VERSION 5.7 ;
  NOWIREEXTENSIONATPIN ON ;
  DIVIDERCHAR "/" ;
  BUSBITCHARS "[]" ;
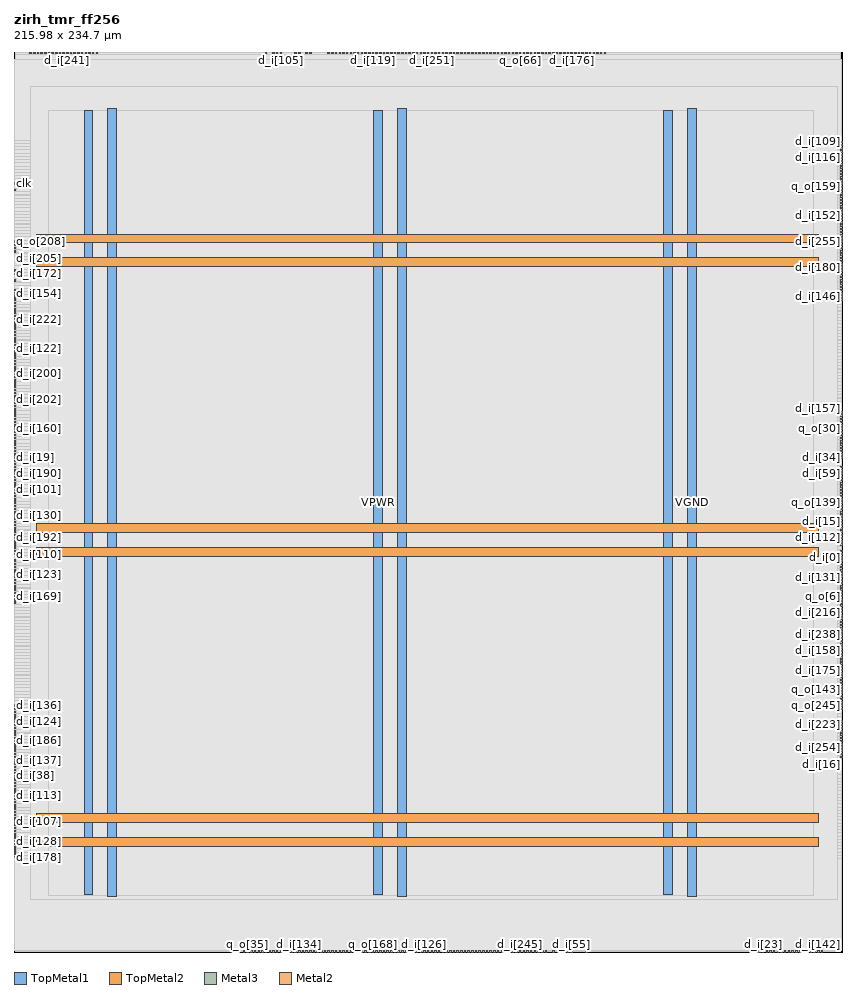
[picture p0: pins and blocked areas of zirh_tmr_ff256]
MACRO zirh_tmr_ff256
  CLASS BLOCK ;
  FOREIGN zirh_tmr_ff256 ;
  ORIGIN 0.000 0.000 ;
  SIZE 215.980 BY 234.700 ;
  PIN VGND
    DIRECTION INOUT ;
    USE GROUND ;
    PORT
      LAYER TopMetal1 ;
        RECT 24.460 14.490 26.660 219.870 ;
    END
    PORT
      LAYER TopMetal1 ;
        RECT 100.060 14.490 102.260 219.870 ;
    END
    PORT
      LAYER TopMetal1 ;
        RECT 175.660 14.490 177.860 219.870 ;
    END
    PORT
      LAYER TopMetal2 ;
        RECT 5.760 33.820 209.760 36.020 ;
    END
    PORT
      LAYER TopMetal2 ;
        RECT 5.760 109.420 209.760 111.620 ;
    END
    PORT
      LAYER TopMetal2 ;
        RECT 5.760 185.020 209.760 187.220 ;
    END
  END VGND
  PIN VPWR
    DIRECTION INOUT ;
    USE POWER ;
    PORT
      LAYER TopMetal1 ;
        RECT 18.260 14.900 20.460 219.460 ;
    END
    PORT
      LAYER TopMetal1 ;
        RECT 93.860 14.900 96.060 219.460 ;
    END
    PORT
      LAYER TopMetal1 ;
        RECT 169.460 14.900 171.660 219.460 ;
    END
    PORT
      LAYER TopMetal2 ;
        RECT 5.760 27.620 209.760 29.820 ;
    END
    PORT
      LAYER TopMetal2 ;
        RECT 5.760 103.220 209.760 105.420 ;
    END
    PORT
      LAYER TopMetal2 ;
        RECT 5.760 178.820 209.760 181.020 ;
    END
  END VPWR
  PIN clk
    DIRECTION INPUT ;
    USE SIGNAL ;
    ANTENNAGATEAREA 1.450800 ;
    PORT
      LAYER Metal3 ;
        RECT 0.000 200.140 0.400 200.540 ;
    END
  END clk
  PIN d_i[0]
    DIRECTION INPUT ;
    USE SIGNAL ;
    ANTENNAGATEAREA 0.180700 ;
    PORT
      LAYER Metal3 ;
        RECT 215.580 102.700 215.980 103.100 ;
    END
  END d_i[0]
  PIN d_i[100]
    DIRECTION INPUT ;
    USE SIGNAL ;
    ANTENNAGATEAREA 0.180700 ;
    PORT
      LAYER Metal2 ;
        RECT 83.800 234.300 84.200 234.700 ;
    END
  END d_i[100]
  PIN d_i[101]
    DIRECTION INPUT ;
    USE SIGNAL ;
    ANTENNAGATEAREA 0.180700 ;
    PORT
      LAYER Metal3 ;
        RECT 0.000 120.340 0.400 120.740 ;
    END
  END d_i[101]
  PIN d_i[102]
    DIRECTION INPUT ;
    USE SIGNAL ;
    ANTENNAGATEAREA 0.180700 ;
    PORT
      LAYER Metal3 ;
        RECT 0.000 132.100 0.400 132.500 ;
    END
  END d_i[102]
  PIN d_i[103]
    DIRECTION INPUT ;
    USE SIGNAL ;
    ANTENNAGATEAREA 0.180700 ;
    PORT
      LAYER Metal2 ;
        RECT 111.640 234.300 112.040 234.700 ;
    END
  END d_i[103]
  PIN d_i[104]
    DIRECTION INPUT ;
    USE SIGNAL ;
    ANTENNAGATEAREA 0.180700 ;
    PORT
      LAYER Metal3 ;
        RECT 0.000 24.580 0.400 24.980 ;
    END
  END d_i[104]
  PIN d_i[105]
    DIRECTION INPUT ;
    USE SIGNAL ;
    ANTENNAGATEAREA 0.180700 ;
    PORT
      LAYER Metal2 ;
        RECT 69.400 234.300 69.800 234.700 ;
    END
  END d_i[105]
  PIN d_i[106]
    DIRECTION INPUT ;
    USE SIGNAL ;
    ANTENNAGATEAREA 0.180700 ;
    PORT
      LAYER Metal3 ;
        RECT 215.580 114.460 215.980 114.860 ;
    END
  END d_i[106]
  PIN d_i[107]
    DIRECTION INPUT ;
    USE SIGNAL ;
    ANTENNAGATEAREA 0.180700 ;
    PORT
      LAYER Metal3 ;
        RECT 0.000 33.820 0.400 34.220 ;
    END
  END d_i[107]
  PIN d_i[108]
    DIRECTION INPUT ;
    USE SIGNAL ;
    ANTENNAGATEAREA 0.180700 ;
    PORT
      LAYER Metal3 ;
        RECT 0.000 172.420 0.400 172.820 ;
    END
  END d_i[108]
  PIN d_i[109]
    DIRECTION INPUT ;
    USE SIGNAL ;
    ANTENNAGATEAREA 0.180700 ;
    PORT
      LAYER Metal3 ;
        RECT 215.580 211.060 215.980 211.460 ;
    END
  END d_i[109]
  PIN d_i[10]
    DIRECTION INPUT ;
    USE SIGNAL ;
    ANTENNAGATEAREA 0.180700 ;
    PORT
      LAYER Metal2 ;
        RECT 109.720 234.300 110.120 234.700 ;
    END
  END d_i[10]
  PIN d_i[110]
    DIRECTION INPUT ;
    USE SIGNAL ;
    ANTENNAGATEAREA 0.180700 ;
    PORT
      LAYER Metal3 ;
        RECT 0.000 103.540 0.400 103.940 ;
    END
  END d_i[110]
  PIN d_i[111]
    DIRECTION INPUT ;
    USE SIGNAL ;
    ANTENNAGATEAREA 0.180700 ;
    PORT
      LAYER Metal3 ;
        RECT 215.580 188.380 215.980 188.780 ;
    END
  END d_i[111]
  PIN d_i[112]
    DIRECTION INPUT ;
    USE SIGNAL ;
    ANTENNAGATEAREA 0.180700 ;
    PORT
      LAYER Metal3 ;
        RECT 215.580 106.060 215.980 106.460 ;
    END
  END d_i[112]
  PIN d_i[113]
    DIRECTION INPUT ;
    USE SIGNAL ;
    ANTENNAGATEAREA 0.180700 ;
    PORT
      LAYER Metal3 ;
        RECT 0.000 40.540 0.400 40.940 ;
    END
  END d_i[113]
  PIN d_i[114]
    DIRECTION INPUT ;
    USE SIGNAL ;
    ANTENNAGATEAREA 0.180700 ;
    PORT
      LAYER Metal2 ;
        RECT 129.880 0.000 130.280 0.400 ;
    END
  END d_i[114]
  PIN d_i[115]
    DIRECTION INPUT ;
    USE SIGNAL ;
    ANTENNAGATEAREA 0.180700 ;
    PORT
      LAYER Metal2 ;
        RECT 153.880 234.300 154.280 234.700 ;
    END
  END d_i[115]
  PIN d_i[116]
    DIRECTION INPUT ;
    USE SIGNAL ;
    ANTENNAGATEAREA 0.180700 ;
    PORT
      LAYER Metal3 ;
        RECT 215.580 206.860 215.980 207.260 ;
    END
  END d_i[116]
  PIN d_i[117]
    DIRECTION INPUT ;
    USE SIGNAL ;
    ANTENNAGATEAREA 0.180700 ;
    PORT
      LAYER Metal3 ;
        RECT 0.000 147.220 0.400 147.620 ;
    END
  END d_i[117]
  PIN d_i[118]
    DIRECTION INPUT ;
    USE SIGNAL ;
    ANTENNAGATEAREA 0.180700 ;
    PORT
      LAYER Metal2 ;
        RECT 152.920 234.300 153.320 234.700 ;
    END
  END d_i[118]
  PIN d_i[119]
    DIRECTION INPUT ;
    USE SIGNAL ;
    ANTENNAGATEAREA 0.180700 ;
    PORT
      LAYER Metal2 ;
        RECT 93.400 234.300 93.800 234.700 ;
    END
  END d_i[119]
  PIN d_i[11]
    DIRECTION INPUT ;
    USE SIGNAL ;
    ANTENNAGATEAREA 0.180700 ;
    PORT
      LAYER Metal2 ;
        RECT 103.000 0.000 103.400 0.400 ;
    END
  END d_i[11]
  PIN d_i[120]
    DIRECTION INPUT ;
    USE SIGNAL ;
    ANTENNAGATEAREA 0.180700 ;
    PORT
      LAYER Metal3 ;
        RECT 215.580 69.940 215.980 70.340 ;
    END
  END d_i[120]
  PIN d_i[121]
    DIRECTION INPUT ;
    USE SIGNAL ;
    ANTENNAGATEAREA 0.180700 ;
    PORT
      LAYER Metal2 ;
        RECT 59.800 0.000 60.200 0.400 ;
    END
  END d_i[121]
  PIN d_i[122]
    DIRECTION INPUT ;
    USE SIGNAL ;
    ANTENNAGATEAREA 0.180700 ;
    PORT
      LAYER Metal3 ;
        RECT 0.000 157.300 0.400 157.700 ;
    END
  END d_i[122]
  PIN d_i[123]
    DIRECTION INPUT ;
    USE SIGNAL ;
    ANTENNAGATEAREA 0.180700 ;
    PORT
      LAYER Metal3 ;
        RECT 0.000 100.180 0.400 100.580 ;
    END
  END d_i[123]
  PIN d_i[124]
    DIRECTION INPUT ;
    USE SIGNAL ;
    ANTENNAGATEAREA 0.180700 ;
    PORT
      LAYER Metal3 ;
        RECT 0.000 59.860 0.400 60.260 ;
    END
  END d_i[124]
  PIN d_i[125]
    DIRECTION INPUT ;
    USE SIGNAL ;
    ANTENNAGATEAREA 0.180700 ;
    PORT
      LAYER Metal3 ;
        RECT 0.000 96.820 0.400 97.220 ;
    END
  END d_i[125]
  PIN d_i[126]
    DIRECTION INPUT ;
    USE SIGNAL ;
    ANTENNAGATEAREA 0.180700 ;
    PORT
      LAYER Metal2 ;
        RECT 106.840 0.000 107.240 0.400 ;
    END
  END d_i[126]
  PIN d_i[127]
    DIRECTION INPUT ;
    USE SIGNAL ;
    ANTENNAGATEAREA 0.180700 ;
    PORT
      LAYER Metal3 ;
        RECT 0.000 35.500 0.400 35.900 ;
    END
  END d_i[127]
  PIN d_i[128]
    DIRECTION INPUT ;
    USE SIGNAL ;
    ANTENNAGATEAREA 0.180700 ;
    PORT
      LAYER Metal3 ;
        RECT 0.000 30.460 0.400 30.860 ;
    END
  END d_i[128]
  PIN d_i[129]
    DIRECTION INPUT ;
    USE SIGNAL ;
    ANTENNAGATEAREA 0.180700 ;
    PORT
      LAYER Metal2 ;
        RECT 126.040 0.000 126.440 0.400 ;
    END
  END d_i[129]
  PIN d_i[12]
    DIRECTION INPUT ;
    USE SIGNAL ;
    ANTENNAGATEAREA 0.180700 ;
    PORT
      LAYER Metal3 ;
        RECT 0.000 132.940 0.400 133.340 ;
    END
  END d_i[12]
  PIN d_i[130]
    DIRECTION INPUT ;
    USE SIGNAL ;
    ANTENNAGATEAREA 0.180700 ;
    PORT
      LAYER Metal3 ;
        RECT 0.000 113.620 0.400 114.020 ;
    END
  END d_i[130]
  PIN d_i[131]
    DIRECTION INPUT ;
    USE SIGNAL ;
    ANTENNAGATEAREA 0.180700 ;
    PORT
      LAYER Metal3 ;
        RECT 215.580 99.340 215.980 99.740 ;
    END
  END d_i[131]
  PIN d_i[132]
    DIRECTION INPUT ;
    USE SIGNAL ;
    ANTENNAGATEAREA 0.180700 ;
    PORT
      LAYER Metal3 ;
        RECT 0.000 145.540 0.400 145.940 ;
    END
  END d_i[132]
  PIN d_i[133]
    DIRECTION INPUT ;
    USE SIGNAL ;
    ANTENNAGATEAREA 0.180700 ;
    PORT
      LAYER Metal2 ;
        RECT 71.320 0.000 71.720 0.400 ;
    END
  END d_i[133]
  PIN d_i[134]
    DIRECTION INPUT ;
    USE SIGNAL ;
    ANTENNAGATEAREA 0.180700 ;
    PORT
      LAYER Metal2 ;
        RECT 74.200 0.000 74.600 0.400 ;
    END
  END d_i[134]
  PIN d_i[135]
    DIRECTION INPUT ;
    USE SIGNAL ;
    ANTENNAGATEAREA 0.180700 ;
    PORT
      LAYER Metal2 ;
        RECT 127.960 0.000 128.360 0.400 ;
    END
  END d_i[135]
  PIN d_i[136]
    DIRECTION INPUT ;
    USE SIGNAL ;
    ANTENNAGATEAREA 0.180700 ;
    PORT
      LAYER Metal3 ;
        RECT 0.000 64.060 0.400 64.460 ;
    END
  END d_i[136]
  PIN d_i[137]
    DIRECTION INPUT ;
    USE SIGNAL ;
    ANTENNAGATEAREA 0.180700 ;
    PORT
      LAYER Metal3 ;
        RECT 0.000 49.780 0.400 50.180 ;
    END
  END d_i[137]
  PIN d_i[138]
    DIRECTION INPUT ;
    USE SIGNAL ;
    ANTENNAGATEAREA 0.180700 ;
    PORT
      LAYER Metal3 ;
        RECT 215.580 206.020 215.980 206.420 ;
    END
  END d_i[138]
  PIN d_i[139]
    DIRECTION INPUT ;
    USE SIGNAL ;
    ANTENNAGATEAREA 0.180700 ;
    PORT
      LAYER Metal3 ;
        RECT 215.580 115.300 215.980 115.700 ;
    END
  END d_i[139]
  PIN d_i[13]
    DIRECTION INPUT ;
    USE SIGNAL ;
    ANTENNAGATEAREA 0.180700 ;
    PORT
      LAYER Metal2 ;
        RECT 121.240 234.300 121.640 234.700 ;
    END
  END d_i[13]
  PIN d_i[140]
    DIRECTION INPUT ;
    USE SIGNAL ;
    ANTENNAGATEAREA 0.180700 ;
    PORT
      LAYER Metal3 ;
        RECT 215.580 72.460 215.980 72.860 ;
    END
  END d_i[140]
  PIN d_i[141]
    DIRECTION INPUT ;
    USE SIGNAL ;
    ANTENNAGATEAREA 0.180700 ;
    PORT
      LAYER Metal3 ;
        RECT 0.000 134.620 0.400 135.020 ;
    END
  END d_i[141]
  PIN d_i[142]
    DIRECTION INPUT ;
    USE SIGNAL ;
    ANTENNAGATEAREA 0.180700 ;
    PORT
      LAYER Metal2 ;
        RECT 210.520 0.000 210.920 0.400 ;
    END
  END d_i[142]
  PIN d_i[143]
    DIRECTION INPUT ;
    USE SIGNAL ;
    ANTENNAGATEAREA 0.180700 ;
    PORT
      LAYER Metal3 ;
        RECT 215.580 66.580 215.980 66.980 ;
    END
  END d_i[143]
  PIN d_i[144]
    DIRECTION INPUT ;
    USE SIGNAL ;
    ANTENNAGATEAREA 0.180700 ;
    PORT
      LAYER Metal3 ;
        RECT 0.000 61.540 0.400 61.940 ;
    END
  END d_i[144]
  PIN d_i[145]
    DIRECTION INPUT ;
    USE SIGNAL ;
    ANTENNAGATEAREA 0.180700 ;
    PORT
      LAYER Metal3 ;
        RECT 0.000 95.140 0.400 95.540 ;
    END
  END d_i[145]
  PIN d_i[146]
    DIRECTION INPUT ;
    USE SIGNAL ;
    ANTENNAGATEAREA 0.180700 ;
    PORT
      LAYER Metal3 ;
        RECT 215.580 170.740 215.980 171.140 ;
    END
  END d_i[146]
  PIN d_i[147]
    DIRECTION INPUT ;
    USE SIGNAL ;
    ANTENNAGATEAREA 0.180700 ;
    PORT
      LAYER Metal2 ;
        RECT 73.240 0.000 73.640 0.400 ;
    END
  END d_i[147]
  PIN d_i[148]
    DIRECTION INPUT ;
    USE SIGNAL ;
    ANTENNAGATEAREA 0.180700 ;
    PORT
      LAYER Metal2 ;
        RECT 69.400 0.000 69.800 0.400 ;
    END
  END d_i[148]
  PIN d_i[149]
    DIRECTION INPUT ;
    USE SIGNAL ;
    ANTENNAGATEAREA 0.180700 ;
    PORT
      LAYER Metal3 ;
        RECT 0.000 122.860 0.400 123.260 ;
    END
  END d_i[149]
  PIN d_i[14]
    DIRECTION INPUT ;
    USE SIGNAL ;
    ANTENNAGATEAREA 0.180700 ;
    PORT
      LAYER Metal3 ;
        RECT 0.000 162.340 0.400 162.740 ;
    END
  END d_i[14]
  PIN d_i[150]
    DIRECTION INPUT ;
    USE SIGNAL ;
    ANTENNAGATEAREA 0.180700 ;
    PORT
      LAYER Metal3 ;
        RECT 215.580 107.740 215.980 108.140 ;
    END
  END d_i[150]
  PIN d_i[151]
    DIRECTION INPUT ;
    USE SIGNAL ;
    ANTENNAGATEAREA 0.180700 ;
    PORT
      LAYER Metal2 ;
        RECT 4.120 234.300 4.520 234.700 ;
    END
  END d_i[151]
  PIN d_i[152]
    DIRECTION INPUT ;
    USE SIGNAL ;
    ANTENNAGATEAREA 0.180700 ;
    PORT
      LAYER Metal3 ;
        RECT 215.580 191.740 215.980 192.140 ;
    END
  END d_i[152]
  PIN d_i[153]
    DIRECTION INPUT ;
    USE SIGNAL ;
    ANTENNAGATEAREA 0.180700 ;
    PORT
      LAYER Metal2 ;
        RECT 97.240 0.000 97.640 0.400 ;
    END
  END d_i[153]
  PIN d_i[154]
    DIRECTION INPUT ;
    USE SIGNAL ;
    ANTENNAGATEAREA 0.180700 ;
    PORT
      LAYER Metal3 ;
        RECT 0.000 171.580 0.400 171.980 ;
    END
  END d_i[154]
  PIN d_i[155]
    DIRECTION INPUT ;
    USE SIGNAL ;
    ANTENNAGATEAREA 0.180700 ;
    PORT
      LAYER Metal3 ;
        RECT 0.000 112.780 0.400 113.180 ;
    END
  END d_i[155]
  PIN d_i[156]
    DIRECTION INPUT ;
    USE SIGNAL ;
    ANTENNAGATEAREA 0.180700 ;
    PORT
      LAYER Metal2 ;
        RECT 199.000 0.000 199.400 0.400 ;
    END
  END d_i[156]
  PIN d_i[157]
    DIRECTION INPUT ;
    USE SIGNAL ;
    ANTENNAGATEAREA 0.180700 ;
    PORT
      LAYER Metal3 ;
        RECT 215.580 139.660 215.980 140.060 ;
    END
  END d_i[157]
  PIN d_i[158]
    DIRECTION INPUT ;
    USE SIGNAL ;
    ANTENNAGATEAREA 0.180700 ;
    PORT
      LAYER Metal3 ;
        RECT 215.580 78.340 215.980 78.740 ;
    END
  END d_i[158]
  PIN d_i[159]
    DIRECTION INPUT ;
    USE SIGNAL ;
    ANTENNAGATEAREA 0.180700 ;
    PORT
      LAYER Metal3 ;
        RECT 215.580 197.620 215.980 198.020 ;
    END
  END d_i[159]
  PIN d_i[15]
    DIRECTION INPUT ;
    USE SIGNAL ;
    ANTENNAGATEAREA 0.180700 ;
    PORT
      LAYER Metal3 ;
        RECT 215.580 110.260 215.980 110.660 ;
    END
  END d_i[15]
  PIN d_i[160]
    DIRECTION INPUT ;
    USE SIGNAL ;
    ANTENNAGATEAREA 0.180700 ;
    PORT
      LAYER Metal3 ;
        RECT 0.000 136.300 0.400 136.700 ;
    END
  END d_i[160]
  PIN d_i[161]
    DIRECTION INPUT ;
    USE SIGNAL ;
    ANTENNAGATEAREA 0.180700 ;
    PORT
      LAYER Metal2 ;
        RECT 207.640 0.000 208.040 0.400 ;
    END
  END d_i[161]
  PIN d_i[162]
    DIRECTION INPUT ;
    USE SIGNAL ;
    ANTENNAGATEAREA 0.180700 ;
    PORT
      LAYER Metal3 ;
        RECT 215.580 184.180 215.980 184.580 ;
    END
  END d_i[162]
  PIN d_i[163]
    DIRECTION INPUT ;
    USE SIGNAL ;
    ANTENNAGATEAREA 0.180700 ;
    PORT
      LAYER Metal3 ;
        RECT 215.580 109.420 215.980 109.820 ;
    END
  END d_i[163]
  PIN d_i[164]
    DIRECTION INPUT ;
    USE SIGNAL ;
    ANTENNAGATEAREA 0.180700 ;
    PORT
      LAYER Metal3 ;
        RECT 0.000 105.220 0.400 105.620 ;
    END
  END d_i[164]
  PIN d_i[165]
    DIRECTION INPUT ;
    USE SIGNAL ;
    ANTENNAGATEAREA 0.180700 ;
    PORT
      LAYER Metal3 ;
        RECT 215.580 175.780 215.980 176.180 ;
    END
  END d_i[165]
  PIN d_i[166]
    DIRECTION INPUT ;
    USE SIGNAL ;
    ANTENNAGATEAREA 0.180700 ;
    PORT
      LAYER Metal2 ;
        RECT 123.160 0.000 123.560 0.400 ;
    END
  END d_i[166]
  PIN d_i[167]
    DIRECTION INPUT ;
    USE SIGNAL ;
    ANTENNAGATEAREA 0.180700 ;
    PORT
      LAYER Metal3 ;
        RECT 0.000 41.380 0.400 41.780 ;
    END
  END d_i[167]
  PIN d_i[168]
    DIRECTION INPUT ;
    USE SIGNAL ;
    ANTENNAGATEAREA 0.180700 ;
    PORT
      LAYER Metal2 ;
        RECT 79.960 0.000 80.360 0.400 ;
    END
  END d_i[168]
  PIN d_i[169]
    DIRECTION INPUT ;
    USE SIGNAL ;
    ANTENNAGATEAREA 0.180700 ;
    PORT
      LAYER Metal3 ;
        RECT 0.000 92.620 0.400 93.020 ;
    END
  END d_i[169]
  PIN d_i[16]
    DIRECTION INPUT ;
    USE SIGNAL ;
    ANTENNAGATEAREA 0.180700 ;
    PORT
      LAYER Metal3 ;
        RECT 215.580 50.620 215.980 51.020 ;
    END
  END d_i[16]
  PIN d_i[170]
    DIRECTION INPUT ;
    USE SIGNAL ;
    ANTENNAGATEAREA 0.180700 ;
    PORT
      LAYER Metal2 ;
        RECT 95.320 234.300 95.720 234.700 ;
    END
  END d_i[170]
  PIN d_i[171]
    DIRECTION INPUT ;
    USE SIGNAL ;
    ANTENNAGATEAREA 0.180700 ;
    PORT
      LAYER Metal3 ;
        RECT 0.000 127.060 0.400 127.460 ;
    END
  END d_i[171]
  PIN d_i[172]
    DIRECTION INPUT ;
    USE SIGNAL ;
    ANTENNAGATEAREA 0.180700 ;
    PORT
      LAYER Metal3 ;
        RECT 0.000 176.620 0.400 177.020 ;
    END
  END d_i[172]
  PIN d_i[173]
    DIRECTION INPUT ;
    USE SIGNAL ;
    ANTENNAGATEAREA 0.180700 ;
    PORT
      LAYER Metal3 ;
        RECT 0.000 116.980 0.400 117.380 ;
    END
  END d_i[173]
  PIN d_i[174]
    DIRECTION INPUT ;
    USE SIGNAL ;
    ANTENNAGATEAREA 0.180700 ;
    PORT
      LAYER Metal3 ;
        RECT 0.000 37.180 0.400 37.580 ;
    END
  END d_i[174]
  PIN d_i[175]
    DIRECTION INPUT ;
    USE SIGNAL ;
    ANTENNAGATEAREA 0.180700 ;
    PORT
      LAYER Metal3 ;
        RECT 215.580 74.980 215.980 75.380 ;
    END
  END d_i[175]
  PIN d_i[176]
    DIRECTION INPUT ;
    USE SIGNAL ;
    ANTENNAGATEAREA 0.180700 ;
    PORT
      LAYER Metal2 ;
        RECT 145.240 234.300 145.640 234.700 ;
    END
  END d_i[176]
  PIN d_i[177]
    DIRECTION INPUT ;
    USE SIGNAL ;
    ANTENNAGATEAREA 0.180700 ;
    PORT
      LAYER Metal2 ;
        RECT 104.920 234.300 105.320 234.700 ;
    END
  END d_i[177]
  PIN d_i[178]
    DIRECTION INPUT ;
    USE SIGNAL ;
    ANTENNAGATEAREA 0.180700 ;
    PORT
      LAYER Metal3 ;
        RECT 0.000 26.260 0.400 26.660 ;
    END
  END d_i[178]
  PIN d_i[179]
    DIRECTION INPUT ;
    USE SIGNAL ;
    ANTENNAGATEAREA 0.180700 ;
    PORT
      LAYER Metal3 ;
        RECT 0.000 99.340 0.400 99.740 ;
    END
  END d_i[179]
  PIN d_i[17]
    DIRECTION INPUT ;
    USE SIGNAL ;
    ANTENNAGATEAREA 0.180700 ;
    PORT
      LAYER Metal2 ;
        RECT 146.200 234.300 146.600 234.700 ;
    END
  END d_i[17]
  PIN d_i[180]
    DIRECTION INPUT ;
    USE SIGNAL ;
    ANTENNAGATEAREA 0.180700 ;
    PORT
      LAYER Metal3 ;
        RECT 215.580 178.300 215.980 178.700 ;
    END
  END d_i[180]
  PIN d_i[181]
    DIRECTION INPUT ;
    USE SIGNAL ;
    ANTENNAGATEAREA 0.180700 ;
    PORT
      LAYER Metal2 ;
        RECT 204.760 0.000 205.160 0.400 ;
    END
  END d_i[181]
  PIN d_i[182]
    DIRECTION INPUT ;
    USE SIGNAL ;
    ANTENNAGATEAREA 0.180700 ;
    PORT
      LAYER Metal3 ;
        RECT 215.580 52.300 215.980 52.700 ;
    END
  END d_i[182]
  PIN d_i[183]
    DIRECTION INPUT ;
    USE SIGNAL ;
    ANTENNAGATEAREA 0.180700 ;
    PORT
      LAYER Metal3 ;
        RECT 0.000 114.460 0.400 114.860 ;
    END
  END d_i[183]
  PIN d_i[184]
    DIRECTION INPUT ;
    USE SIGNAL ;
    ANTENNAGATEAREA 0.180700 ;
    PORT
      LAYER Metal3 ;
        RECT 0.000 174.940 0.400 175.340 ;
    END
  END d_i[184]
  PIN d_i[185]
    DIRECTION INPUT ;
    USE SIGNAL ;
    ANTENNAGATEAREA 0.180700 ;
    PORT
      LAYER Metal2 ;
        RECT 61.720 0.000 62.120 0.400 ;
    END
  END d_i[185]
  PIN d_i[186]
    DIRECTION INPUT ;
    USE SIGNAL ;
    ANTENNAGATEAREA 0.180700 ;
    PORT
      LAYER Metal3 ;
        RECT 0.000 53.140 0.400 53.540 ;
    END
  END d_i[186]
  PIN d_i[187]
    DIRECTION INPUT ;
    USE SIGNAL ;
    ANTENNAGATEAREA 0.180700 ;
    PORT
      LAYER Metal3 ;
        RECT 0.000 27.940 0.400 28.340 ;
    END
  END d_i[187]
  PIN d_i[188]
    DIRECTION INPUT ;
    USE SIGNAL ;
    ANTENNAGATEAREA 0.180700 ;
    PORT
      LAYER Metal2 ;
        RECT 83.800 0.000 84.200 0.400 ;
    END
  END d_i[188]
  PIN d_i[189]
    DIRECTION INPUT ;
    USE SIGNAL ;
    ANTENNAGATEAREA 0.180700 ;
    PORT
      LAYER Metal2 ;
        RECT 86.680 0.000 87.080 0.400 ;
    END
  END d_i[189]
  PIN d_i[18]
    DIRECTION INPUT ;
    USE SIGNAL ;
    ANTENNAGATEAREA 0.180700 ;
    PORT
      LAYER Metal2 ;
        RECT 68.440 0.000 68.840 0.400 ;
    END
  END d_i[18]
  PIN d_i[190]
    DIRECTION INPUT ;
    USE SIGNAL ;
    ANTENNAGATEAREA 0.180700 ;
    PORT
      LAYER Metal3 ;
        RECT 0.000 124.540 0.400 124.940 ;
    END
  END d_i[190]
  PIN d_i[191]
    DIRECTION INPUT ;
    USE SIGNAL ;
    ANTENNAGATEAREA 0.180700 ;
    PORT
      LAYER Metal3 ;
        RECT 215.580 100.180 215.980 100.580 ;
    END
  END d_i[191]
  PIN d_i[192]
    DIRECTION INPUT ;
    USE SIGNAL ;
    ANTENNAGATEAREA 0.180700 ;
    PORT
      LAYER Metal3 ;
        RECT 0.000 106.060 0.400 106.460 ;
    END
  END d_i[192]
  PIN d_i[193]
    DIRECTION INPUT ;
    USE SIGNAL ;
    ANTENNAGATEAREA 0.180700 ;
    PORT
      LAYER Metal3 ;
        RECT 0.000 106.900 0.400 107.300 ;
    END
  END d_i[193]
  PIN d_i[194]
    DIRECTION INPUT ;
    USE SIGNAL ;
    ANTENNAGATEAREA 0.180700 ;
    PORT
      LAYER Metal2 ;
        RECT 151.960 234.300 152.360 234.700 ;
    END
  END d_i[194]
  PIN d_i[195]
    DIRECTION INPUT ;
    USE SIGNAL ;
    ANTENNAGATEAREA 0.180700 ;
    PORT
      LAYER Metal2 ;
        RECT 133.720 0.000 134.120 0.400 ;
    END
  END d_i[195]
  PIN d_i[196]
    DIRECTION INPUT ;
    USE SIGNAL ;
    ANTENNAGATEAREA 0.180700 ;
    PORT
      LAYER Metal3 ;
        RECT 0.000 119.500 0.400 119.900 ;
    END
  END d_i[196]
  PIN d_i[197]
    DIRECTION INPUT ;
    USE SIGNAL ;
    ANTENNAGATEAREA 0.180700 ;
    PORT
      LAYER Metal3 ;
        RECT 215.580 76.660 215.980 77.060 ;
    END
  END d_i[197]
  PIN d_i[198]
    DIRECTION INPUT ;
    USE SIGNAL ;
    ANTENNAGATEAREA 0.180700 ;
    PORT
      LAYER Metal3 ;
        RECT 0.000 163.180 0.400 163.580 ;
    END
  END d_i[198]
  PIN d_i[199]
    DIRECTION INPUT ;
    USE SIGNAL ;
    ANTENNAGATEAREA 0.180700 ;
    PORT
      LAYER Metal3 ;
        RECT 0.000 109.420 0.400 109.820 ;
    END
  END d_i[199]
  PIN d_i[19]
    DIRECTION INPUT ;
    USE SIGNAL ;
    ANTENNAGATEAREA 0.180700 ;
    PORT
      LAYER Metal3 ;
        RECT 0.000 128.740 0.400 129.140 ;
    END
  END d_i[19]
  PIN d_i[1]
    DIRECTION INPUT ;
    USE SIGNAL ;
    ANTENNAGATEAREA 0.180700 ;
    PORT
      LAYER Metal3 ;
        RECT 215.580 202.660 215.980 203.060 ;
    END
  END d_i[1]
  PIN d_i[200]
    DIRECTION INPUT ;
    USE SIGNAL ;
    ANTENNAGATEAREA 0.180700 ;
    PORT
      LAYER Metal3 ;
        RECT 0.000 150.580 0.400 150.980 ;
    END
  END d_i[200]
  PIN d_i[201]
    DIRECTION INPUT ;
    USE SIGNAL ;
    ANTENNAGATEAREA 0.180700 ;
    PORT
      LAYER Metal3 ;
        RECT 0.000 116.140 0.400 116.540 ;
    END
  END d_i[201]
  PIN d_i[202]
    DIRECTION INPUT ;
    USE SIGNAL ;
    ANTENNAGATEAREA 0.180700 ;
    PORT
      LAYER Metal3 ;
        RECT 0.000 143.860 0.400 144.260 ;
    END
  END d_i[202]
  PIN d_i[203]
    DIRECTION INPUT ;
    USE SIGNAL ;
    ANTENNAGATEAREA 0.180700 ;
    PORT
      LAYER Metal3 ;
        RECT 0.000 90.940 0.400 91.340 ;
    END
  END d_i[203]
  PIN d_i[204]
    DIRECTION INPUT ;
    USE SIGNAL ;
    ANTENNAGATEAREA 0.180700 ;
    PORT
      LAYER Metal2 ;
        RECT 7.000 234.300 7.400 234.700 ;
    END
  END d_i[204]
  PIN d_i[205]
    DIRECTION INPUT ;
    USE SIGNAL ;
    ANTENNAGATEAREA 0.180700 ;
    PORT
      LAYER Metal3 ;
        RECT 0.000 182.500 0.400 182.900 ;
    END
  END d_i[205]
  PIN d_i[206]
    DIRECTION INPUT ;
    USE SIGNAL ;
    ANTENNAGATEAREA 0.180700 ;
    PORT
      LAYER Metal3 ;
        RECT 0.000 146.380 0.400 146.780 ;
    END
  END d_i[206]
  PIN d_i[207]
    DIRECTION INPUT ;
    USE SIGNAL ;
    ANTENNAGATEAREA 0.180700 ;
    PORT
      LAYER Metal3 ;
        RECT 0.000 48.940 0.400 49.340 ;
    END
  END d_i[207]
  PIN d_i[208]
    DIRECTION INPUT ;
    USE SIGNAL ;
    ANTENNAGATEAREA 0.180700 ;
    PORT
      LAYER Metal3 ;
        RECT 0.000 184.180 0.400 184.580 ;
    END
  END d_i[208]
  PIN d_i[209]
    DIRECTION INPUT ;
    USE SIGNAL ;
    ANTENNAGATEAREA 0.180700 ;
    PORT
      LAYER Metal2 ;
        RECT 80.920 0.000 81.320 0.400 ;
    END
  END d_i[209]
  PIN d_i[20]
    DIRECTION INPUT ;
    USE SIGNAL ;
    ANTENNAGATEAREA 0.180700 ;
    PORT
      LAYER Metal3 ;
        RECT 0.000 170.740 0.400 171.140 ;
    END
  END d_i[20]
  PIN d_i[210]
    DIRECTION INPUT ;
    USE SIGNAL ;
    ANTENNAGATEAREA 0.180700 ;
    PORT
      LAYER Metal2 ;
        RECT 107.800 0.000 108.200 0.400 ;
    END
  END d_i[210]
  PIN d_i[211]
    DIRECTION INPUT ;
    USE SIGNAL ;
    ANTENNAGATEAREA 0.180700 ;
    PORT
      LAYER Metal2 ;
        RECT 138.520 234.300 138.920 234.700 ;
    END
  END d_i[211]
  PIN d_i[212]
    DIRECTION INPUT ;
    USE SIGNAL ;
    ANTENNAGATEAREA 0.180700 ;
    PORT
      LAYER Metal3 ;
        RECT 215.580 112.780 215.980 113.180 ;
    END
  END d_i[212]
  PIN d_i[213]
    DIRECTION INPUT ;
    USE SIGNAL ;
    ANTENNAGATEAREA 0.180700 ;
    PORT
      LAYER Metal3 ;
        RECT 215.580 122.860 215.980 123.260 ;
    END
  END d_i[213]
  PIN d_i[214]
    DIRECTION INPUT ;
    USE SIGNAL ;
    ANTENNAGATEAREA 0.180700 ;
    PORT
      LAYER Metal2 ;
        RECT 91.480 234.300 91.880 234.700 ;
    END
  END d_i[214]
  PIN d_i[215]
    DIRECTION INPUT ;
    USE SIGNAL ;
    ANTENNAGATEAREA 0.180700 ;
    PORT
      LAYER Metal3 ;
        RECT 215.580 201.820 215.980 202.220 ;
    END
  END d_i[215]
  PIN d_i[216]
    DIRECTION INPUT ;
    USE SIGNAL ;
    ANTENNAGATEAREA 0.180700 ;
    PORT
      LAYER Metal3 ;
        RECT 215.580 88.420 215.980 88.820 ;
    END
  END d_i[216]
  PIN d_i[217]
    DIRECTION INPUT ;
    USE SIGNAL ;
    ANTENNAGATEAREA 0.180700 ;
    PORT
      LAYER Metal2 ;
        RECT 103.960 234.300 104.360 234.700 ;
    END
  END d_i[217]
  PIN d_i[218]
    DIRECTION INPUT ;
    USE SIGNAL ;
    ANTENNAGATEAREA 0.180700 ;
    PORT
      LAYER Metal2 ;
        RECT 105.880 0.000 106.280 0.400 ;
    END
  END d_i[218]
  PIN d_i[219]
    DIRECTION INPUT ;
    USE SIGNAL ;
    ANTENNAGATEAREA 0.180700 ;
    PORT
      LAYER Metal2 ;
        RECT 125.080 0.000 125.480 0.400 ;
    END
  END d_i[219]
  PIN d_i[21]
    DIRECTION INPUT ;
    USE SIGNAL ;
    ANTENNAGATEAREA 0.180700 ;
    PORT
      LAYER Metal2 ;
        RECT 123.160 234.300 123.560 234.700 ;
    END
  END d_i[21]
  PIN d_i[220]
    DIRECTION INPUT ;
    USE SIGNAL ;
    ANTENNAGATEAREA 0.180700 ;
    PORT
      LAYER Metal2 ;
        RECT 129.880 234.300 130.280 234.700 ;
    END
  END d_i[220]
  PIN d_i[221]
    DIRECTION INPUT ;
    USE SIGNAL ;
    ANTENNAGATEAREA 0.180700 ;
    PORT
      LAYER Metal3 ;
        RECT 0.000 108.580 0.400 108.980 ;
    END
  END d_i[221]
  PIN d_i[222]
    DIRECTION INPUT ;
    USE SIGNAL ;
    ANTENNAGATEAREA 0.180700 ;
    PORT
      LAYER Metal3 ;
        RECT 0.000 164.860 0.400 165.260 ;
    END
  END d_i[222]
  PIN d_i[223]
    DIRECTION INPUT ;
    USE SIGNAL ;
    ANTENNAGATEAREA 0.180700 ;
    PORT
      LAYER Metal3 ;
        RECT 215.580 59.020 215.980 59.420 ;
    END
  END d_i[223]
  PIN d_i[224]
    DIRECTION INPUT ;
    USE SIGNAL ;
    ANTENNAGATEAREA 0.180700 ;
    PORT
      LAYER Metal3 ;
        RECT 0.000 140.500 0.400 140.900 ;
    END
  END d_i[224]
  PIN d_i[225]
    DIRECTION INPUT ;
    USE SIGNAL ;
    ANTENNAGATEAREA 0.180700 ;
    PORT
      LAYER Metal2 ;
        RECT 148.120 234.300 148.520 234.700 ;
    END
  END d_i[225]
  PIN d_i[226]
    DIRECTION INPUT ;
    USE SIGNAL ;
    ANTENNAGATEAREA 0.180700 ;
    PORT
      LAYER Metal2 ;
        RECT 137.560 234.300 137.960 234.700 ;
    END
  END d_i[226]
  PIN d_i[227]
    DIRECTION INPUT ;
    USE SIGNAL ;
    ANTENNAGATEAREA 0.180700 ;
    PORT
      LAYER Metal3 ;
        RECT 0.000 54.820 0.400 55.220 ;
    END
  END d_i[227]
  PIN d_i[228]
    DIRECTION INPUT ;
    USE SIGNAL ;
    ANTENNAGATEAREA 0.180700 ;
    PORT
      LAYER Metal2 ;
        RECT 122.200 0.000 122.600 0.400 ;
    END
  END d_i[228]
  PIN d_i[229]
    DIRECTION INPUT ;
    USE SIGNAL ;
    ANTENNAGATEAREA 0.180700 ;
    PORT
      LAYER Metal3 ;
        RECT 0.000 158.980 0.400 159.380 ;
    END
  END d_i[229]
  PIN d_i[22]
    DIRECTION INPUT ;
    USE SIGNAL ;
    ANTENNAGATEAREA 0.180700 ;
    PORT
      LAYER Metal2 ;
        RECT 112.600 0.000 113.000 0.400 ;
    END
  END d_i[22]
  PIN d_i[230]
    DIRECTION INPUT ;
    USE SIGNAL ;
    ANTENNAGATEAREA 0.180700 ;
    PORT
      LAYER Metal3 ;
        RECT 215.580 65.740 215.980 66.140 ;
    END
  END d_i[230]
  PIN d_i[231]
    DIRECTION INPUT ;
    USE SIGNAL ;
    ANTENNAGATEAREA 0.180700 ;
    PORT
      LAYER Metal3 ;
        RECT 0.000 153.100 0.400 153.500 ;
    END
  END d_i[231]
  PIN d_i[232]
    DIRECTION INPUT ;
    USE SIGNAL ;
    ANTENNAGATEAREA 0.180700 ;
    PORT
      LAYER Metal2 ;
        RECT 198.040 0.000 198.440 0.400 ;
    END
  END d_i[232]
  PIN d_i[233]
    DIRECTION INPUT ;
    USE SIGNAL ;
    ANTENNAGATEAREA 0.180700 ;
    PORT
      LAYER Metal2 ;
        RECT 120.280 234.300 120.680 234.700 ;
    END
  END d_i[233]
  PIN d_i[234]
    DIRECTION INPUT ;
    USE SIGNAL ;
    ANTENNAGATEAREA 0.180700 ;
    PORT
      LAYER Metal3 ;
        RECT 0.000 139.660 0.400 140.060 ;
    END
  END d_i[234]
  PIN d_i[235]
    DIRECTION INPUT ;
    USE SIGNAL ;
    ANTENNAGATEAREA 0.180700 ;
    PORT
      LAYER Metal2 ;
        RECT 82.840 234.300 83.240 234.700 ;
    END
  END d_i[235]
  PIN d_i[236]
    DIRECTION INPUT ;
    USE SIGNAL ;
    ANTENNAGATEAREA 0.180700 ;
    PORT
      LAYER Metal2 ;
        RECT 99.160 0.000 99.560 0.400 ;
    END
  END d_i[236]
  PIN d_i[237]
    DIRECTION INPUT ;
    USE SIGNAL ;
    ANTENNAGATEAREA 0.180700 ;
    PORT
      LAYER Metal2 ;
        RECT 203.800 0.000 204.200 0.400 ;
    END
  END d_i[237]
  PIN d_i[238]
    DIRECTION INPUT ;
    USE SIGNAL ;
    ANTENNAGATEAREA 0.180700 ;
    PORT
      LAYER Metal3 ;
        RECT 215.580 82.540 215.980 82.940 ;
    END
  END d_i[238]
  PIN d_i[239]
    DIRECTION INPUT ;
    USE SIGNAL ;
    ANTENNAGATEAREA 0.180700 ;
    PORT
      LAYER Metal3 ;
        RECT 215.580 169.900 215.980 170.300 ;
    END
  END d_i[239]
  PIN d_i[23]
    DIRECTION INPUT ;
    USE SIGNAL ;
    ANTENNAGATEAREA 0.180700 ;
    PORT
      LAYER Metal2 ;
        RECT 195.160 0.000 195.560 0.400 ;
    END
  END d_i[23]
  PIN d_i[240]
    DIRECTION INPUT ;
    USE SIGNAL ;
    ANTENNAGATEAREA 0.180700 ;
    PORT
      LAYER Metal2 ;
        RECT 130.840 0.000 131.240 0.400 ;
    END
  END d_i[240]
  PIN d_i[241]
    DIRECTION INPUT ;
    USE SIGNAL ;
    ANTENNAGATEAREA 0.180700 ;
    PORT
      LAYER Metal2 ;
        RECT 13.720 234.300 14.120 234.700 ;
    END
  END d_i[241]
  PIN d_i[242]
    DIRECTION INPUT ;
    USE SIGNAL ;
    ANTENNAGATEAREA 0.180700 ;
    PORT
      LAYER Metal3 ;
        RECT 215.580 119.500 215.980 119.900 ;
    END
  END d_i[242]
  PIN d_i[243]
    DIRECTION INPUT ;
    USE SIGNAL ;
    ANTENNAGATEAREA 0.180700 ;
    PORT
      LAYER Metal2 ;
        RECT 151.000 234.300 151.400 234.700 ;
    END
  END d_i[243]
  PIN d_i[244]
    DIRECTION INPUT ;
    USE SIGNAL ;
    ANTENNAGATEAREA 0.180700 ;
    PORT
      LAYER Metal3 ;
        RECT 215.580 86.740 215.980 87.140 ;
    END
  END d_i[244]
  PIN d_i[245]
    DIRECTION INPUT ;
    USE SIGNAL ;
    ANTENNAGATEAREA 0.180700 ;
    PORT
      LAYER Metal2 ;
        RECT 131.800 0.000 132.200 0.400 ;
    END
  END d_i[245]
  PIN d_i[246]
    DIRECTION INPUT ;
    USE SIGNAL ;
    ANTENNAGATEAREA 0.180700 ;
    PORT
      LAYER Metal2 ;
        RECT 5.080 234.300 5.480 234.700 ;
    END
  END d_i[246]
  PIN d_i[247]
    DIRECTION INPUT ;
    USE SIGNAL ;
    ANTENNAGATEAREA 0.180700 ;
    PORT
      LAYER Metal2 ;
        RECT 116.440 234.300 116.840 234.700 ;
    END
  END d_i[247]
  PIN d_i[248]
    DIRECTION INPUT ;
    USE SIGNAL ;
    ANTENNAGATEAREA 0.180700 ;
    PORT
      LAYER Metal3 ;
        RECT 0.000 58.180 0.400 58.580 ;
    END
  END d_i[248]
  PIN d_i[249]
    DIRECTION INPUT ;
    USE SIGNAL ;
    ANTENNAGATEAREA 0.180700 ;
    PORT
      LAYER Metal2 ;
        RECT 118.360 0.000 118.760 0.400 ;
    END
  END d_i[249]
  PIN d_i[24]
    DIRECTION INPUT ;
    USE SIGNAL ;
    ANTENNAGATEAREA 0.180700 ;
    PORT
      LAYER Metal2 ;
        RECT 150.040 234.300 150.440 234.700 ;
    END
  END d_i[24]
  PIN d_i[250]
    DIRECTION INPUT ;
    USE SIGNAL ;
    ANTENNAGATEAREA 0.180700 ;
    PORT
      LAYER Metal3 ;
        RECT 215.580 208.540 215.980 208.940 ;
    END
  END d_i[250]
  PIN d_i[251]
    DIRECTION INPUT ;
    USE SIGNAL ;
    ANTENNAGATEAREA 0.180700 ;
    PORT
      LAYER Metal2 ;
        RECT 108.760 234.300 109.160 234.700 ;
    END
  END d_i[251]
  PIN d_i[252]
    DIRECTION INPUT ;
    USE SIGNAL ;
    ANTENNAGATEAREA 0.180700 ;
    PORT
      LAYER Metal3 ;
        RECT 0.000 123.700 0.400 124.100 ;
    END
  END d_i[252]
  PIN d_i[253]
    DIRECTION INPUT ;
    USE SIGNAL ;
    ANTENNAGATEAREA 0.180700 ;
    PORT
      LAYER Metal2 ;
        RECT 138.520 0.000 138.920 0.400 ;
    END
  END d_i[253]
  PIN d_i[254]
    DIRECTION INPUT ;
    USE SIGNAL ;
    ANTENNAGATEAREA 0.180700 ;
    PORT
      LAYER Metal3 ;
        RECT 215.580 53.140 215.980 53.540 ;
    END
  END d_i[254]
  PIN d_i[255]
    DIRECTION INPUT ;
    USE SIGNAL ;
    ANTENNAGATEAREA 0.180700 ;
    PORT
      LAYER Metal3 ;
        RECT 215.580 185.020 215.980 185.420 ;
    END
  END d_i[255]
  PIN d_i[25]
    DIRECTION INPUT ;
    USE SIGNAL ;
    ANTENNAGATEAREA 0.180700 ;
    PORT
      LAYER Metal3 ;
        RECT 215.580 89.260 215.980 89.660 ;
    END
  END d_i[25]
  PIN d_i[26]
    DIRECTION INPUT ;
    USE SIGNAL ;
    ANTENNAGATEAREA 0.180700 ;
    PORT
      LAYER Metal3 ;
        RECT 0.000 154.780 0.400 155.180 ;
    END
  END d_i[26]
  PIN d_i[27]
    DIRECTION INPUT ;
    USE SIGNAL ;
    ANTENNAGATEAREA 0.180700 ;
    PORT
      LAYER Metal3 ;
        RECT 0.000 48.100 0.400 48.500 ;
    END
  END d_i[27]
  PIN d_i[28]
    DIRECTION INPUT ;
    USE SIGNAL ;
    ANTENNAGATEAREA 0.180700 ;
    PORT
      LAYER Metal2 ;
        RECT 77.080 234.300 77.480 234.700 ;
    END
  END d_i[28]
  PIN d_i[29]
    DIRECTION INPUT ;
    USE SIGNAL ;
    ANTENNAGATEAREA 0.180700 ;
    PORT
      LAYER Metal3 ;
        RECT 0.000 160.660 0.400 161.060 ;
    END
  END d_i[29]
  PIN d_i[2]
    DIRECTION INPUT ;
    USE SIGNAL ;
    ANTENNAGATEAREA 0.180700 ;
    PORT
      LAYER Metal2 ;
        RECT 88.600 234.300 89.000 234.700 ;
    END
  END d_i[2]
  PIN d_i[30]
    DIRECTION INPUT ;
    USE SIGNAL ;
    ANTENNAGATEAREA 0.180700 ;
    PORT
      LAYER Metal3 ;
        RECT 215.580 135.460 215.980 135.860 ;
    END
  END d_i[30]
  PIN d_i[31]
    DIRECTION INPUT ;
    USE SIGNAL ;
    ANTENNAGATEAREA 0.180700 ;
    PORT
      LAYER Metal2 ;
        RECT 101.080 234.300 101.480 234.700 ;
    END
  END d_i[31]
  PIN d_i[32]
    DIRECTION INPUT ;
    USE SIGNAL ;
    ANTENNAGATEAREA 0.180700 ;
    PORT
      LAYER Metal3 ;
        RECT 215.580 85.060 215.980 85.460 ;
    END
  END d_i[32]
  PIN d_i[33]
    DIRECTION INPUT ;
    USE SIGNAL ;
    ANTENNAGATEAREA 0.180700 ;
    PORT
      LAYER Metal3 ;
        RECT 0.000 55.660 0.400 56.060 ;
    END
  END d_i[33]
  PIN d_i[34]
    DIRECTION INPUT ;
    USE SIGNAL ;
    ANTENNAGATEAREA 0.180700 ;
    PORT
      LAYER Metal3 ;
        RECT 215.580 128.740 215.980 129.140 ;
    END
  END d_i[34]
  PIN d_i[35]
    DIRECTION INPUT ;
    USE SIGNAL ;
    ANTENNAGATEAREA 0.180700 ;
    PORT
      LAYER Metal2 ;
        RECT 62.680 0.000 63.080 0.400 ;
    END
  END d_i[35]
  PIN d_i[36]
    DIRECTION INPUT ;
    USE SIGNAL ;
    ANTENNAGATEAREA 0.180700 ;
    PORT
      LAYER Metal3 ;
        RECT 0.000 148.900 0.400 149.300 ;
    END
  END d_i[36]
  PIN d_i[37]
    DIRECTION INPUT ;
    USE SIGNAL ;
    ANTENNAGATEAREA 0.180700 ;
    PORT
      LAYER Metal2 ;
        RECT 84.760 234.300 85.160 234.700 ;
    END
  END d_i[37]
  PIN d_i[38]
    DIRECTION INPUT ;
    USE SIGNAL ;
    ANTENNAGATEAREA 0.180700 ;
    PORT
      LAYER Metal3 ;
        RECT 0.000 43.900 0.400 44.300 ;
    END
  END d_i[38]
  PIN d_i[39]
    DIRECTION INPUT ;
    USE SIGNAL ;
    ANTENNAGATEAREA 0.180700 ;
    PORT
      LAYER Metal2 ;
        RECT 144.280 234.300 144.680 234.700 ;
    END
  END d_i[39]
  PIN d_i[3]
    DIRECTION INPUT ;
    USE SIGNAL ;
    ANTENNAGATEAREA 0.180700 ;
    PORT
      LAYER Metal2 ;
        RECT 11.800 234.300 12.200 234.700 ;
    END
  END d_i[3]
  PIN d_i[40]
    DIRECTION INPUT ;
    USE SIGNAL ;
    ANTENNAGATEAREA 0.180700 ;
    PORT
      LAYER Metal3 ;
        RECT 215.580 56.500 215.980 56.900 ;
    END
  END d_i[40]
  PIN d_i[41]
    DIRECTION INPUT ;
    USE SIGNAL ;
    ANTENNAGATEAREA 0.180700 ;
    PORT
      LAYER Metal2 ;
        RECT 102.040 0.000 102.440 0.400 ;
    END
  END d_i[41]
  PIN d_i[42]
    DIRECTION INPUT ;
    USE SIGNAL ;
    ANTENNAGATEAREA 0.180700 ;
    PORT
      LAYER Metal2 ;
        RECT 127.000 234.300 127.400 234.700 ;
    END
  END d_i[42]
  PIN d_i[43]
    DIRECTION INPUT ;
    USE SIGNAL ;
    ANTENNAGATEAREA 0.180700 ;
    PORT
      LAYER Metal2 ;
        RECT 78.040 0.000 78.440 0.400 ;
    END
  END d_i[43]
  PIN d_i[44]
    DIRECTION INPUT ;
    USE SIGNAL ;
    ANTENNAGATEAREA 0.180700 ;
    PORT
      LAYER Metal3 ;
        RECT 215.580 193.420 215.980 193.820 ;
    END
  END d_i[44]
  PIN d_i[45]
    DIRECTION INPUT ;
    USE SIGNAL ;
    ANTENNAGATEAREA 0.180700 ;
    PORT
      LAYER Metal3 ;
        RECT 0.000 31.300 0.400 31.700 ;
    END
  END d_i[45]
  PIN d_i[46]
    DIRECTION INPUT ;
    USE SIGNAL ;
    ANTENNAGATEAREA 0.180700 ;
    PORT
      LAYER Metal3 ;
        RECT 215.580 174.940 215.980 175.340 ;
    END
  END d_i[46]
  PIN d_i[47]
    DIRECTION INPUT ;
    USE SIGNAL ;
    ANTENNAGATEAREA 0.180700 ;
    PORT
      LAYER Metal3 ;
        RECT 0.000 158.140 0.400 158.540 ;
    END
  END d_i[47]
  PIN d_i[48]
    DIRECTION INPUT ;
    USE SIGNAL ;
    ANTENNAGATEAREA 0.180700 ;
    PORT
      LAYER Metal2 ;
        RECT 79.000 0.000 79.400 0.400 ;
    END
  END d_i[48]
  PIN d_i[49]
    DIRECTION INPUT ;
    USE SIGNAL ;
    ANTENNAGATEAREA 0.180700 ;
    PORT
      LAYER Metal3 ;
        RECT 215.580 131.260 215.980 131.660 ;
    END
  END d_i[49]
  PIN d_i[4]
    DIRECTION INPUT ;
    USE SIGNAL ;
    ANTENNAGATEAREA 0.180700 ;
    PORT
      LAYER Metal2 ;
        RECT 85.720 234.300 86.120 234.700 ;
    END
  END d_i[4]
  PIN d_i[50]
    DIRECTION INPUT ;
    USE SIGNAL ;
    ANTENNAGATEAREA 0.180700 ;
    PORT
      LAYER Metal3 ;
        RECT 215.580 171.580 215.980 171.980 ;
    END
  END d_i[50]
  PIN d_i[51]
    DIRECTION INPUT ;
    USE SIGNAL ;
    ANTENNAGATEAREA 0.180700 ;
    PORT
      LAYER Metal2 ;
        RECT 21.400 234.300 21.800 234.700 ;
    END
  END d_i[51]
  PIN d_i[52]
    DIRECTION INPUT ;
    USE SIGNAL ;
    ANTENNAGATEAREA 0.180700 ;
    PORT
      LAYER Metal2 ;
        RECT 142.360 234.300 142.760 234.700 ;
    END
  END d_i[52]
  PIN d_i[53]
    DIRECTION INPUT ;
    USE SIGNAL ;
    ANTENNAGATEAREA 0.180700 ;
    PORT
      LAYER Metal3 ;
        RECT 0.000 167.380 0.400 167.780 ;
    END
  END d_i[53]
  PIN d_i[54]
    DIRECTION INPUT ;
    USE SIGNAL ;
    ANTENNAGATEAREA 0.180700 ;
    PORT
      LAYER Metal3 ;
        RECT 0.000 56.500 0.400 56.900 ;
    END
  END d_i[54]
  PIN d_i[55]
    DIRECTION INPUT ;
    USE SIGNAL ;
    ANTENNAGATEAREA 0.180700 ;
    PORT
      LAYER Metal2 ;
        RECT 145.240 0.000 145.640 0.400 ;
    END
  END d_i[55]
  PIN d_i[56]
    DIRECTION INPUT ;
    USE SIGNAL ;
    ANTENNAGATEAREA 0.180700 ;
    PORT
      LAYER Metal2 ;
        RECT 96.280 234.300 96.680 234.700 ;
    END
  END d_i[56]
  PIN d_i[57]
    DIRECTION INPUT ;
    USE SIGNAL ;
    ANTENNAGATEAREA 0.180700 ;
    PORT
      LAYER Metal3 ;
        RECT 215.580 94.300 215.980 94.700 ;
    END
  END d_i[57]
  PIN d_i[58]
    DIRECTION INPUT ;
    USE SIGNAL ;
    ANTENNAGATEAREA 0.180700 ;
    PORT
      LAYER Metal3 ;
        RECT 0.000 32.140 0.400 32.540 ;
    END
  END d_i[58]
  PIN d_i[59]
    DIRECTION INPUT ;
    USE SIGNAL ;
    ANTENNAGATEAREA 0.180700 ;
    PORT
      LAYER Metal3 ;
        RECT 215.580 124.540 215.980 124.940 ;
    END
  END d_i[59]
  PIN d_i[5]
    DIRECTION INPUT ;
    USE SIGNAL ;
    ANTENNAGATEAREA 0.180700 ;
    PORT
      LAYER Metal3 ;
        RECT 215.580 63.220 215.980 63.620 ;
    END
  END d_i[5]
  PIN d_i[60]
    DIRECTION INPUT ;
    USE SIGNAL ;
    ANTENNAGATEAREA 0.180700 ;
    PORT
      LAYER Metal3 ;
        RECT 215.580 200.980 215.980 201.380 ;
    END
  END d_i[60]
  PIN d_i[61]
    DIRECTION INPUT ;
    USE SIGNAL ;
    ANTENNAGATEAREA 0.180700 ;
    PORT
      LAYER Metal3 ;
        RECT 215.580 87.580 215.980 87.980 ;
    END
  END d_i[61]
  PIN d_i[62]
    DIRECTION INPUT ;
    USE SIGNAL ;
    ANTENNAGATEAREA 0.180700 ;
    PORT
      LAYER Metal3 ;
        RECT 215.580 91.780 215.980 92.180 ;
    END
  END d_i[62]
  PIN d_i[63]
    DIRECTION INPUT ;
    USE SIGNAL ;
    ANTENNAGATEAREA 0.180700 ;
    PORT
      LAYER Metal2 ;
        RECT 101.080 0.000 101.480 0.400 ;
    END
  END d_i[63]
  PIN d_i[64]
    DIRECTION INPUT ;
    USE SIGNAL ;
    ANTENNAGATEAREA 0.180700 ;
    PORT
      LAYER Metal2 ;
        RECT 113.560 0.000 113.960 0.400 ;
    END
  END d_i[64]
  PIN d_i[65]
    DIRECTION INPUT ;
    USE SIGNAL ;
    ANTENNAGATEAREA 0.180700 ;
    PORT
      LAYER Metal3 ;
        RECT 215.580 132.100 215.980 132.500 ;
    END
  END d_i[65]
  PIN d_i[66]
    DIRECTION INPUT ;
    USE SIGNAL ;
    ANTENNAGATEAREA 0.180700 ;
    PORT
      LAYER Metal2 ;
        RECT 117.400 234.300 117.800 234.700 ;
    END
  END d_i[66]
  PIN d_i[67]
    DIRECTION INPUT ;
    USE SIGNAL ;
    ANTENNAGATEAREA 0.180700 ;
    PORT
      LAYER Metal3 ;
        RECT 0.000 27.100 0.400 27.500 ;
    END
  END d_i[67]
  PIN d_i[68]
    DIRECTION INPUT ;
    USE SIGNAL ;
    ANTENNAGATEAREA 0.180700 ;
    PORT
      LAYER Metal2 ;
        RECT 18.520 234.300 18.920 234.700 ;
    END
  END d_i[68]
  PIN d_i[69]
    DIRECTION INPUT ;
    USE SIGNAL ;
    ANTENNAGATEAREA 0.180700 ;
    PORT
      LAYER Metal2 ;
        RECT 10.840 234.300 11.240 234.700 ;
    END
  END d_i[69]
  PIN d_i[6]
    DIRECTION INPUT ;
    USE SIGNAL ;
    ANTENNAGATEAREA 0.180700 ;
    PORT
      LAYER Metal3 ;
        RECT 215.580 80.020 215.980 80.420 ;
    END
  END d_i[6]
  PIN d_i[70]
    DIRECTION INPUT ;
    USE SIGNAL ;
    ANTENNAGATEAREA 0.180700 ;
    PORT
      LAYER Metal2 ;
        RECT 76.120 0.000 76.520 0.400 ;
    END
  END d_i[70]
  PIN d_i[71]
    DIRECTION INPUT ;
    USE SIGNAL ;
    ANTENNAGATEAREA 0.180700 ;
    PORT
      LAYER Metal3 ;
        RECT 0.000 52.300 0.400 52.700 ;
    END
  END d_i[71]
  PIN d_i[72]
    DIRECTION INPUT ;
    USE SIGNAL ;
    ANTENNAGATEAREA 0.180700 ;
    PORT
      LAYER Metal2 ;
        RECT 94.360 234.300 94.760 234.700 ;
    END
  END d_i[72]
  PIN d_i[73]
    DIRECTION INPUT ;
    USE SIGNAL ;
    ANTENNAGATEAREA 0.180700 ;
    PORT
      LAYER Metal3 ;
        RECT 215.580 185.860 215.980 186.260 ;
    END
  END d_i[73]
  PIN d_i[74]
    DIRECTION INPUT ;
    USE SIGNAL ;
    ANTENNAGATEAREA 0.180700 ;
    PORT
      LAYER Metal2 ;
        RECT 108.760 0.000 109.160 0.400 ;
    END
  END d_i[74]
  PIN d_i[75]
    DIRECTION INPUT ;
    USE SIGNAL ;
    ANTENNAGATEAREA 0.180700 ;
    PORT
      LAYER Metal2 ;
        RECT 98.200 234.300 98.600 234.700 ;
    END
  END d_i[75]
  PIN d_i[76]
    DIRECTION INPUT ;
    USE SIGNAL ;
    ANTENNAGATEAREA 0.180700 ;
    PORT
      LAYER Metal3 ;
        RECT 215.580 132.940 215.980 133.340 ;
    END
  END d_i[76]
  PIN d_i[77]
    DIRECTION INPUT ;
    USE SIGNAL ;
    ANTENNAGATEAREA 0.180700 ;
    PORT
      LAYER Metal2 ;
        RECT 87.640 0.000 88.040 0.400 ;
    END
  END d_i[77]
  PIN d_i[78]
    DIRECTION INPUT ;
    USE SIGNAL ;
    ANTENNAGATEAREA 0.180700 ;
    PORT
      LAYER Metal3 ;
        RECT 0.000 95.980 0.400 96.380 ;
    END
  END d_i[78]
  PIN d_i[79]
    DIRECTION INPUT ;
    USE SIGNAL ;
    ANTENNAGATEAREA 0.180700 ;
    PORT
      LAYER Metal2 ;
        RECT 200.920 0.000 201.320 0.400 ;
    END
  END d_i[79]
  PIN d_i[7]
    DIRECTION INPUT ;
    USE SIGNAL ;
    ANTENNAGATEAREA 0.180700 ;
    PORT
      LAYER Metal2 ;
        RECT 15.640 234.300 16.040 234.700 ;
    END
  END d_i[7]
  PIN d_i[80]
    DIRECTION INPUT ;
    USE SIGNAL ;
    ANTENNAGATEAREA 0.180700 ;
    PORT
      LAYER Metal3 ;
        RECT 215.580 97.660 215.980 98.060 ;
    END
  END d_i[80]
  PIN d_i[81]
    DIRECTION INPUT ;
    USE SIGNAL ;
    ANTENNAGATEAREA 0.180700 ;
    PORT
      LAYER Metal2 ;
        RECT 140.440 0.000 140.840 0.400 ;
    END
  END d_i[81]
  PIN d_i[82]
    DIRECTION INPUT ;
    USE SIGNAL ;
    ANTENNAGATEAREA 0.180700 ;
    PORT
      LAYER Metal2 ;
        RECT 9.880 234.300 10.280 234.700 ;
    END
  END d_i[82]
  PIN d_i[83]
    DIRECTION INPUT ;
    USE SIGNAL ;
    ANTENNAGATEAREA 0.180700 ;
    PORT
      LAYER Metal3 ;
        RECT 215.580 137.140 215.980 137.540 ;
    END
  END d_i[83]
  PIN d_i[84]
    DIRECTION INPUT ;
    USE SIGNAL ;
    ANTENNAGATEAREA 0.180700 ;
    PORT
      LAYER Metal3 ;
        RECT 0.000 47.260 0.400 47.660 ;
    END
  END d_i[84]
  PIN d_i[85]
    DIRECTION INPUT ;
    USE SIGNAL ;
    ANTENNAGATEAREA 0.180700 ;
    PORT
      LAYER Metal3 ;
        RECT 0.000 126.220 0.400 126.620 ;
    END
  END d_i[85]
  PIN d_i[86]
    DIRECTION INPUT ;
    USE SIGNAL ;
    ANTENNAGATEAREA 0.180700 ;
    PORT
      LAYER Metal3 ;
        RECT 215.580 113.620 215.980 114.020 ;
    END
  END d_i[86]
  PIN d_i[87]
    DIRECTION INPUT ;
    USE SIGNAL ;
    ANTENNAGATEAREA 0.180700 ;
    PORT
      LAYER Metal3 ;
        RECT 0.000 153.940 0.400 154.340 ;
    END
  END d_i[87]
  PIN d_i[88]
    DIRECTION INPUT ;
    USE SIGNAL ;
    ANTENNAGATEAREA 0.180700 ;
    PORT
      LAYER Metal3 ;
        RECT 0.000 53.980 0.400 54.380 ;
    END
  END d_i[88]
  PIN d_i[89]
    DIRECTION INPUT ;
    USE SIGNAL ;
    ANTENNAGATEAREA 0.180700 ;
    PORT
      LAYER Metal2 ;
        RECT 98.200 0.000 98.600 0.400 ;
    END
  END d_i[89]
  PIN d_i[8]
    DIRECTION INPUT ;
    USE SIGNAL ;
    ANTENNAGATEAREA 0.180700 ;
    PORT
      LAYER Metal2 ;
        RECT 8.920 234.300 9.320 234.700 ;
    END
  END d_i[8]
  PIN d_i[90]
    DIRECTION INPUT ;
    USE SIGNAL ;
    ANTENNAGATEAREA 0.180700 ;
    PORT
      LAYER Metal2 ;
        RECT 135.640 234.300 136.040 234.700 ;
    END
  END d_i[90]
  PIN d_i[91]
    DIRECTION INPUT ;
    USE SIGNAL ;
    ANTENNAGATEAREA 0.180700 ;
    PORT
      LAYER Metal3 ;
        RECT 215.580 103.540 215.980 103.940 ;
    END
  END d_i[91]
  PIN d_i[92]
    DIRECTION INPUT ;
    USE SIGNAL ;
    ANTENNAGATEAREA 0.180700 ;
    PORT
      LAYER Metal2 ;
        RECT 89.560 234.300 89.960 234.700 ;
    END
  END d_i[92]
  PIN d_i[93]
    DIRECTION INPUT ;
    USE SIGNAL ;
    ANTENNAGATEAREA 0.180700 ;
    PORT
      LAYER Metal3 ;
        RECT 215.580 57.340 215.980 57.740 ;
    END
  END d_i[93]
  PIN d_i[94]
    DIRECTION INPUT ;
    USE SIGNAL ;
    ANTENNAGATEAREA 0.180700 ;
    PORT
      LAYER Metal3 ;
        RECT 215.580 123.700 215.980 124.100 ;
    END
  END d_i[94]
  PIN d_i[95]
    DIRECTION INPUT ;
    USE SIGNAL ;
    ANTENNAGATEAREA 0.180700 ;
    PORT
      LAYER Metal3 ;
        RECT 0.000 42.220 0.400 42.620 ;
    END
  END d_i[95]
  PIN d_i[96]
    DIRECTION INPUT ;
    USE SIGNAL ;
    ANTENNAGATEAREA 0.180700 ;
    PORT
      LAYER Metal2 ;
        RECT 12.760 234.300 13.160 234.700 ;
    END
  END d_i[96]
  PIN d_i[97]
    DIRECTION INPUT ;
    USE SIGNAL ;
    ANTENNAGATEAREA 0.180700 ;
    PORT
      LAYER Metal3 ;
        RECT 215.580 71.620 215.980 72.020 ;
    END
  END d_i[97]
  PIN d_i[98]
    DIRECTION INPUT ;
    USE SIGNAL ;
    ANTENNAGATEAREA 0.180700 ;
    PORT
      LAYER Metal2 ;
        RECT 110.680 234.300 111.080 234.700 ;
    END
  END d_i[98]
  PIN d_i[99]
    DIRECTION INPUT ;
    USE SIGNAL ;
    ANTENNAGATEAREA 0.180700 ;
    PORT
      LAYER Metal2 ;
        RECT 88.600 0.000 89.000 0.400 ;
    END
  END d_i[99]
  PIN d_i[9]
    DIRECTION INPUT ;
    USE SIGNAL ;
    ANTENNAGATEAREA 0.180700 ;
    PORT
      LAYER Metal3 ;
        RECT 215.580 179.140 215.980 179.540 ;
    END
  END d_i[9]
  PIN q_o[0]
    DIRECTION OUTPUT ;
    USE SIGNAL ;
    ANTENNADIFFAREA 0.708600 ;
    PORT
      LAYER Metal3 ;
        RECT 215.580 101.860 215.980 102.260 ;
    END
  END q_o[0]
  PIN q_o[100]
    DIRECTION OUTPUT ;
    USE SIGNAL ;
    ANTENNADIFFAREA 0.708600 ;
    PORT
      LAYER Metal2 ;
        RECT 128.920 234.300 129.320 234.700 ;
    END
  END q_o[100]
  PIN q_o[101]
    DIRECTION OUTPUT ;
    USE SIGNAL ;
    ANTENNADIFFAREA 0.708600 ;
    PORT
      LAYER Metal3 ;
        RECT 0.000 122.020 0.400 122.420 ;
    END
  END q_o[101]
  PIN q_o[102]
    DIRECTION OUTPUT ;
    USE SIGNAL ;
    ANTENNADIFFAREA 0.708600 ;
    PORT
      LAYER Metal3 ;
        RECT 0.000 133.780 0.400 134.180 ;
    END
  END q_o[102]
  PIN q_o[103]
    DIRECTION OUTPUT ;
    USE SIGNAL ;
    ANTENNADIFFAREA 0.708600 ;
    PORT
      LAYER Metal2 ;
        RECT 127.960 234.300 128.360 234.700 ;
    END
  END q_o[103]
  PIN q_o[104]
    DIRECTION OUTPUT ;
    USE SIGNAL ;
    ANTENNADIFFAREA 0.708600 ;
    PORT
      LAYER Metal3 ;
        RECT 0.000 36.340 0.400 36.740 ;
    END
  END q_o[104]
  PIN q_o[105]
    DIRECTION OUTPUT ;
    USE SIGNAL ;
    ANTENNADIFFAREA 0.708600 ;
    PORT
      LAYER Metal2 ;
        RECT 81.880 234.300 82.280 234.700 ;
    END
  END q_o[105]
  PIN q_o[106]
    DIRECTION OUTPUT ;
    USE SIGNAL ;
    ANTENNADIFFAREA 0.708600 ;
    PORT
      LAYER Metal3 ;
        RECT 215.580 118.660 215.980 119.060 ;
    END
  END q_o[106]
  PIN q_o[107]
    DIRECTION OUTPUT ;
    USE SIGNAL ;
    ANTENNADIFFAREA 0.708600 ;
    PORT
      LAYER Metal2 ;
        RECT 70.360 0.000 70.760 0.400 ;
    END
  END q_o[107]
  PIN q_o[108]
    DIRECTION OUTPUT ;
    USE SIGNAL ;
    ANTENNADIFFAREA 0.708600 ;
    PORT
      LAYER Metal2 ;
        RECT 86.680 234.300 87.080 234.700 ;
    END
  END q_o[108]
  PIN q_o[109]
    DIRECTION OUTPUT ;
    USE SIGNAL ;
    ANTENNADIFFAREA 0.708600 ;
    PORT
      LAYER Metal3 ;
        RECT 215.580 189.220 215.980 189.620 ;
    END
  END q_o[109]
  PIN q_o[10]
    DIRECTION OUTPUT ;
    USE SIGNAL ;
    ANTENNADIFFAREA 0.708600 ;
    PORT
      LAYER Metal2 ;
        RECT 124.120 234.300 124.520 234.700 ;
    END
  END q_o[10]
  PIN q_o[110]
    DIRECTION OUTPUT ;
    USE SIGNAL ;
    ANTENNADIFFAREA 0.708600 ;
    PORT
      LAYER Metal3 ;
        RECT 0.000 104.380 0.400 104.780 ;
    END
  END q_o[110]
  PIN q_o[111]
    DIRECTION OUTPUT ;
    USE SIGNAL ;
    ANTENNADIFFAREA 0.708600 ;
    PORT
      LAYER Metal3 ;
        RECT 215.580 179.980 215.980 180.380 ;
    END
  END q_o[111]
  PIN q_o[112]
    DIRECTION OUTPUT ;
    USE SIGNAL ;
    ANTENNADIFFAREA 0.708600 ;
    PORT
      LAYER Metal3 ;
        RECT 215.580 106.900 215.980 107.300 ;
    END
  END q_o[112]
  PIN q_o[113]
    DIRECTION OUTPUT ;
    USE SIGNAL ;
    ANTENNADIFFAREA 0.708600 ;
    PORT
      LAYER Metal3 ;
        RECT 0.000 63.220 0.400 63.620 ;
    END
  END q_o[113]
  PIN q_o[114]
    DIRECTION OUTPUT ;
    USE SIGNAL ;
    ANTENNADIFFAREA 0.708600 ;
    PORT
      LAYER Metal2 ;
        RECT 137.560 0.000 137.960 0.400 ;
    END
  END q_o[114]
  PIN q_o[115]
    DIRECTION OUTPUT ;
    USE SIGNAL ;
    ANTENNADIFFAREA 0.708600 ;
    PORT
      LAYER Metal3 ;
        RECT 215.580 195.940 215.980 196.340 ;
    END
  END q_o[115]
  PIN q_o[116]
    DIRECTION OUTPUT ;
    USE SIGNAL ;
    ANTENNADIFFAREA 0.708600 ;
    PORT
      LAYER Metal3 ;
        RECT 215.580 195.100 215.980 195.500 ;
    END
  END q_o[116]
  PIN q_o[117]
    DIRECTION OUTPUT ;
    USE SIGNAL ;
    ANTENNADIFFAREA 0.708600 ;
    PORT
      LAYER Metal3 ;
        RECT 0.000 148.060 0.400 148.460 ;
    END
  END q_o[117]
  PIN q_o[118]
    DIRECTION OUTPUT ;
    USE SIGNAL ;
    ANTENNADIFFAREA 0.708600 ;
    PORT
      LAYER Metal2 ;
        RECT 134.680 234.300 135.080 234.700 ;
    END
  END q_o[118]
  PIN q_o[119]
    DIRECTION OUTPUT ;
    USE SIGNAL ;
    ANTENNADIFFAREA 0.708600 ;
    PORT
      LAYER Metal2 ;
        RECT 149.080 234.300 149.480 234.700 ;
    END
  END q_o[119]
  PIN q_o[11]
    DIRECTION OUTPUT ;
    USE SIGNAL ;
    ANTENNADIFFAREA 0.708600 ;
    PORT
      LAYER Metal2 ;
        RECT 120.280 0.000 120.680 0.400 ;
    END
  END q_o[11]
  PIN q_o[120]
    DIRECTION OUTPUT ;
    USE SIGNAL ;
    ANTENNADIFFAREA 0.708600 ;
    PORT
      LAYER Metal3 ;
        RECT 215.580 70.780 215.980 71.180 ;
    END
  END q_o[120]
  PIN q_o[121]
    DIRECTION OUTPUT ;
    USE SIGNAL ;
    ANTENNADIFFAREA 0.708600 ;
    PORT
      LAYER Metal2 ;
        RECT 81.880 0.000 82.280 0.400 ;
    END
  END q_o[121]
  PIN q_o[122]
    DIRECTION OUTPUT ;
    USE SIGNAL ;
    ANTENNADIFFAREA 0.708600 ;
    PORT
      LAYER Metal3 ;
        RECT 0.000 156.460 0.400 156.860 ;
    END
  END q_o[122]
  PIN q_o[123]
    DIRECTION OUTPUT ;
    USE SIGNAL ;
    ANTENNADIFFAREA 0.708600 ;
    PORT
      LAYER Metal3 ;
        RECT 0.000 101.860 0.400 102.260 ;
    END
  END q_o[123]
  PIN q_o[124]
    DIRECTION OUTPUT ;
    USE SIGNAL ;
    ANTENNADIFFAREA 0.708600 ;
    PORT
      LAYER Metal3 ;
        RECT 0.000 50.620 0.400 51.020 ;
    END
  END q_o[124]
  PIN q_o[125]
    DIRECTION OUTPUT ;
    USE SIGNAL ;
    ANTENNADIFFAREA 0.708600 ;
    PORT
      LAYER Metal3 ;
        RECT 0.000 98.500 0.400 98.900 ;
    END
  END q_o[125]
  PIN q_o[126]
    DIRECTION OUTPUT ;
    USE SIGNAL ;
    ANTENNADIFFAREA 0.708600 ;
    PORT
      LAYER Metal2 ;
        RECT 117.400 0.000 117.800 0.400 ;
    END
  END q_o[126]
  PIN q_o[127]
    DIRECTION OUTPUT ;
    USE SIGNAL ;
    ANTENNADIFFAREA 0.708600 ;
    PORT
      LAYER Metal3 ;
        RECT 0.000 38.860 0.400 39.260 ;
    END
  END q_o[127]
  PIN q_o[128]
    DIRECTION OUTPUT ;
    USE SIGNAL ;
    ANTENNADIFFAREA 0.708600 ;
    PORT
      LAYER Metal3 ;
        RECT 0.000 32.980 0.400 33.380 ;
    END
  END q_o[128]
  PIN q_o[129]
    DIRECTION OUTPUT ;
    USE SIGNAL ;
    ANTENNADIFFAREA 0.708600 ;
    PORT
      LAYER Metal3 ;
        RECT 215.580 69.100 215.980 69.500 ;
    END
  END q_o[129]
  PIN q_o[12]
    DIRECTION OUTPUT ;
    USE SIGNAL ;
    ANTENNADIFFAREA 0.708600 ;
    PORT
      LAYER Metal3 ;
        RECT 0.000 135.460 0.400 135.860 ;
    END
  END q_o[12]
  PIN q_o[130]
    DIRECTION OUTPUT ;
    USE SIGNAL ;
    ANTENNADIFFAREA 0.708600 ;
    PORT
      LAYER Metal2 ;
        RECT 100.120 0.000 100.520 0.400 ;
    END
  END q_o[130]
  PIN q_o[131]
    DIRECTION OUTPUT ;
    USE SIGNAL ;
    ANTENNADIFFAREA 0.708600 ;
    PORT
      LAYER Metal3 ;
        RECT 215.580 95.140 215.980 95.540 ;
    END
  END q_o[131]
  PIN q_o[132]
    DIRECTION OUTPUT ;
    USE SIGNAL ;
    ANTENNADIFFAREA 0.708600 ;
    PORT
      LAYER Metal3 ;
        RECT 0.000 144.700 0.400 145.100 ;
    END
  END q_o[132]
  PIN q_o[133]
    DIRECTION OUTPUT ;
    USE SIGNAL ;
    ANTENNADIFFAREA 0.708600 ;
    PORT
      LAYER Metal2 ;
        RECT 84.760 0.000 85.160 0.400 ;
    END
  END q_o[133]
  PIN q_o[134]
    DIRECTION OUTPUT ;
    USE SIGNAL ;
    ANTENNADIFFAREA 0.708600 ;
    PORT
      LAYER Metal2 ;
        RECT 90.520 0.000 90.920 0.400 ;
    END
  END q_o[134]
  PIN q_o[135]
    DIRECTION OUTPUT ;
    USE SIGNAL ;
    ANTENNADIFFAREA 0.708600 ;
    PORT
      LAYER Metal3 ;
        RECT 215.580 96.820 215.980 97.220 ;
    END
  END q_o[135]
  PIN q_o[136]
    DIRECTION OUTPUT ;
    USE SIGNAL ;
    ANTENNADIFFAREA 0.708600 ;
    PORT
      LAYER Metal3 ;
        RECT 0.000 46.420 0.400 46.820 ;
    END
  END q_o[136]
  PIN q_o[137]
    DIRECTION OUTPUT ;
    USE SIGNAL ;
    ANTENNADIFFAREA 0.708600 ;
    PORT
      LAYER Metal3 ;
        RECT 0.000 57.340 0.400 57.740 ;
    END
  END q_o[137]
  PIN q_o[138]
    DIRECTION OUTPUT ;
    USE SIGNAL ;
    ANTENNADIFFAREA 0.708600 ;
    PORT
      LAYER Metal3 ;
        RECT 215.580 205.180 215.980 205.580 ;
    END
  END q_o[138]
  PIN q_o[139]
    DIRECTION OUTPUT ;
    USE SIGNAL ;
    ANTENNADIFFAREA 0.708600 ;
    PORT
      LAYER Metal3 ;
        RECT 215.580 116.980 215.980 117.380 ;
    END
  END q_o[139]
  PIN q_o[13]
    DIRECTION OUTPUT ;
    USE SIGNAL ;
    ANTENNADIFFAREA 0.708600 ;
    PORT
      LAYER Metal3 ;
        RECT 215.580 122.020 215.980 122.420 ;
    END
  END q_o[13]
  PIN q_o[140]
    DIRECTION OUTPUT ;
    USE SIGNAL ;
    ANTENNADIFFAREA 0.708600 ;
    PORT
      LAYER Metal3 ;
        RECT 215.580 74.140 215.980 74.540 ;
    END
  END q_o[140]
  PIN q_o[141]
    DIRECTION OUTPUT ;
    USE SIGNAL ;
    ANTENNADIFFAREA 0.708600 ;
    PORT
      LAYER Metal3 ;
        RECT 0.000 137.140 0.400 137.540 ;
    END
  END q_o[141]
  PIN q_o[142]
    DIRECTION OUTPUT ;
    USE SIGNAL ;
    ANTENNADIFFAREA 0.708600 ;
    PORT
      LAYER Metal2 ;
        RECT 209.560 0.000 209.960 0.400 ;
    END
  END q_o[142]
  PIN q_o[143]
    DIRECTION OUTPUT ;
    USE SIGNAL ;
    ANTENNADIFFAREA 0.708600 ;
    PORT
      LAYER Metal3 ;
        RECT 215.580 68.260 215.980 68.660 ;
    END
  END q_o[143]
  PIN q_o[144]
    DIRECTION OUTPUT ;
    USE SIGNAL ;
    ANTENNADIFFAREA 0.708600 ;
    PORT
      LAYER Metal2 ;
        RECT 65.560 0.000 65.960 0.400 ;
    END
  END q_o[144]
  PIN q_o[145]
    DIRECTION OUTPUT ;
    USE SIGNAL ;
    ANTENNADIFFAREA 0.708600 ;
    PORT
      LAYER Metal2 ;
        RECT 77.080 0.000 77.480 0.400 ;
    END
  END q_o[145]
  PIN q_o[146]
    DIRECTION OUTPUT ;
    USE SIGNAL ;
    ANTENNADIFFAREA 0.708600 ;
    PORT
      LAYER Metal3 ;
        RECT 215.580 186.700 215.980 187.100 ;
    END
  END q_o[146]
  PIN q_o[147]
    DIRECTION OUTPUT ;
    USE SIGNAL ;
    ANTENNADIFFAREA 0.708600 ;
    PORT
      LAYER Metal2 ;
        RECT 95.320 0.000 95.720 0.400 ;
    END
  END q_o[147]
  PIN q_o[148]
    DIRECTION OUTPUT ;
    USE SIGNAL ;
    ANTENNADIFFAREA 0.708600 ;
    PORT
      LAYER Metal2 ;
        RECT 82.840 0.000 83.240 0.400 ;
    END
  END q_o[148]
  PIN q_o[149]
    DIRECTION OUTPUT ;
    USE SIGNAL ;
    ANTENNADIFFAREA 0.708600 ;
    PORT
      LAYER Metal3 ;
        RECT 0.000 125.380 0.400 125.780 ;
    END
  END q_o[149]
  PIN q_o[14]
    DIRECTION OUTPUT ;
    USE SIGNAL ;
    ANTENNADIFFAREA 0.708600 ;
    PORT
      LAYER Metal3 ;
        RECT 0.000 164.020 0.400 164.420 ;
    END
  END q_o[14]
  PIN q_o[150]
    DIRECTION OUTPUT ;
    USE SIGNAL ;
    ANTENNADIFFAREA 0.708600 ;
    PORT
      LAYER Metal3 ;
        RECT 215.580 111.100 215.980 111.500 ;
    END
  END q_o[150]
  PIN q_o[151]
    DIRECTION OUTPUT ;
    USE SIGNAL ;
    ANTENNADIFFAREA 0.708600 ;
    PORT
      LAYER Metal2 ;
        RECT 19.480 234.300 19.880 234.700 ;
    END
  END q_o[151]
  PIN q_o[152]
    DIRECTION OUTPUT ;
    USE SIGNAL ;
    ANTENNADIFFAREA 0.708600 ;
    PORT
      LAYER Metal3 ;
        RECT 215.580 209.380 215.980 209.780 ;
    END
  END q_o[152]
  PIN q_o[153]
    DIRECTION OUTPUT ;
    USE SIGNAL ;
    ANTENNADIFFAREA 0.708600 ;
    PORT
      LAYER Metal2 ;
        RECT 111.640 0.000 112.040 0.400 ;
    END
  END q_o[153]
  PIN q_o[154]
    DIRECTION OUTPUT ;
    USE SIGNAL ;
    ANTENNADIFFAREA 0.708600 ;
    PORT
      LAYER Metal3 ;
        RECT 0.000 169.060 0.400 169.460 ;
    END
  END q_o[154]
  PIN q_o[155]
    DIRECTION OUTPUT ;
    USE SIGNAL ;
    ANTENNADIFFAREA 0.708600 ;
    PORT
      LAYER Metal2 ;
        RECT 96.280 0.000 96.680 0.400 ;
    END
  END q_o[155]
  PIN q_o[156]
    DIRECTION OUTPUT ;
    USE SIGNAL ;
    ANTENNADIFFAREA 0.708600 ;
    PORT
      LAYER Metal2 ;
        RECT 208.600 0.000 209.000 0.400 ;
    END
  END q_o[156]
  PIN q_o[157]
    DIRECTION OUTPUT ;
    USE SIGNAL ;
    ANTENNADIFFAREA 0.708600 ;
    PORT
      LAYER Metal3 ;
        RECT 215.580 140.500 215.980 140.900 ;
    END
  END q_o[157]
  PIN q_o[158]
    DIRECTION OUTPUT ;
    USE SIGNAL ;
    ANTENNADIFFAREA 0.708600 ;
    PORT
      LAYER Metal3 ;
        RECT 215.580 90.940 215.980 91.340 ;
    END
  END q_o[158]
  PIN q_o[159]
    DIRECTION OUTPUT ;
    USE SIGNAL ;
    ANTENNADIFFAREA 0.708600 ;
    PORT
      LAYER Metal3 ;
        RECT 215.580 199.300 215.980 199.700 ;
    END
  END q_o[159]
  PIN q_o[15]
    DIRECTION OUTPUT ;
    USE SIGNAL ;
    ANTENNADIFFAREA 0.708600 ;
    PORT
      LAYER Metal3 ;
        RECT 215.580 108.580 215.980 108.980 ;
    END
  END q_o[15]
  PIN q_o[160]
    DIRECTION OUTPUT ;
    USE SIGNAL ;
    ANTENNADIFFAREA 0.708600 ;
    PORT
      LAYER Metal3 ;
        RECT 0.000 137.980 0.400 138.380 ;
    END
  END q_o[160]
  PIN q_o[161]
    DIRECTION OUTPUT ;
    USE SIGNAL ;
    ANTENNADIFFAREA 0.708600 ;
    PORT
      LAYER Metal2 ;
        RECT 196.120 0.000 196.520 0.400 ;
    END
  END q_o[161]
  PIN q_o[162]
    DIRECTION OUTPUT ;
    USE SIGNAL ;
    ANTENNADIFFAREA 0.708600 ;
    PORT
      LAYER Metal3 ;
        RECT 215.580 180.820 215.980 181.220 ;
    END
  END q_o[162]
  PIN q_o[163]
    DIRECTION OUTPUT ;
    USE SIGNAL ;
    ANTENNADIFFAREA 0.708600 ;
    PORT
      LAYER Metal3 ;
        RECT 215.580 111.940 215.980 112.340 ;
    END
  END q_o[163]
  PIN q_o[164]
    DIRECTION OUTPUT ;
    USE SIGNAL ;
    ANTENNADIFFAREA 0.708600 ;
    PORT
      LAYER Metal3 ;
        RECT 0.000 111.100 0.400 111.500 ;
    END
  END q_o[164]
  PIN q_o[165]
    DIRECTION OUTPUT ;
    USE SIGNAL ;
    ANTENNADIFFAREA 0.708600 ;
    PORT
      LAYER Metal3 ;
        RECT 215.580 203.500 215.980 203.900 ;
    END
  END q_o[165]
  PIN q_o[166]
    DIRECTION OUTPUT ;
    USE SIGNAL ;
    ANTENNADIFFAREA 0.708600 ;
    PORT
      LAYER Metal2 ;
        RECT 136.600 0.000 137.000 0.400 ;
    END
  END q_o[166]
  PIN q_o[167]
    DIRECTION OUTPUT ;
    USE SIGNAL ;
    ANTENNADIFFAREA 0.708600 ;
    PORT
      LAYER Metal2 ;
        RECT 64.600 0.000 65.000 0.400 ;
    END
  END q_o[167]
  PIN q_o[168]
    DIRECTION OUTPUT ;
    USE SIGNAL ;
    ANTENNADIFFAREA 0.708600 ;
    PORT
      LAYER Metal2 ;
        RECT 93.400 0.000 93.800 0.400 ;
    END
  END q_o[168]
  PIN q_o[169]
    DIRECTION OUTPUT ;
    USE SIGNAL ;
    ANTENNADIFFAREA 0.708600 ;
    PORT
      LAYER Metal3 ;
        RECT 0.000 94.300 0.400 94.700 ;
    END
  END q_o[169]
  PIN q_o[16]
    DIRECTION OUTPUT ;
    USE SIGNAL ;
    ANTENNADIFFAREA 0.708600 ;
    PORT
      LAYER Metal3 ;
        RECT 215.580 51.460 215.980 51.860 ;
    END
  END q_o[16]
  PIN q_o[170]
    DIRECTION OUTPUT ;
    USE SIGNAL ;
    ANTENNADIFFAREA 0.708600 ;
    PORT
      LAYER Metal2 ;
        RECT 115.480 234.300 115.880 234.700 ;
    END
  END q_o[170]
  PIN q_o[171]
    DIRECTION OUTPUT ;
    USE SIGNAL ;
    ANTENNADIFFAREA 0.708600 ;
    PORT
      LAYER Metal3 ;
        RECT 0.000 127.900 0.400 128.300 ;
    END
  END q_o[171]
  PIN q_o[172]
    DIRECTION OUTPUT ;
    USE SIGNAL ;
    ANTENNADIFFAREA 0.708600 ;
    PORT
      LAYER Metal3 ;
        RECT 0.000 177.460 0.400 177.860 ;
    END
  END q_o[172]
  PIN q_o[173]
    DIRECTION OUTPUT ;
    USE SIGNAL ;
    ANTENNADIFFAREA 0.708600 ;
    PORT
      LAYER Metal3 ;
        RECT 0.000 118.660 0.400 119.060 ;
    END
  END q_o[173]
  PIN q_o[174]
    DIRECTION OUTPUT ;
    USE SIGNAL ;
    ANTENNADIFFAREA 0.708600 ;
    PORT
      LAYER Metal3 ;
        RECT 0.000 39.700 0.400 40.100 ;
    END
  END q_o[174]
  PIN q_o[175]
    DIRECTION OUTPUT ;
    USE SIGNAL ;
    ANTENNADIFFAREA 0.708600 ;
    PORT
      LAYER Metal3 ;
        RECT 215.580 75.820 215.980 76.220 ;
    END
  END q_o[175]
  PIN q_o[176]
    DIRECTION OUTPUT ;
    USE SIGNAL ;
    ANTENNADIFFAREA 0.708600 ;
    PORT
      LAYER Metal3 ;
        RECT 215.580 196.780 215.980 197.180 ;
    END
  END q_o[176]
  PIN q_o[177]
    DIRECTION OUTPUT ;
    USE SIGNAL ;
    ANTENNADIFFAREA 0.708600 ;
    PORT
      LAYER Metal2 ;
        RECT 119.320 234.300 119.720 234.700 ;
    END
  END q_o[177]
  PIN q_o[178]
    DIRECTION OUTPUT ;
    USE SIGNAL ;
    ANTENNADIFFAREA 0.708600 ;
    PORT
      LAYER Metal3 ;
        RECT 0.000 38.020 0.400 38.420 ;
    END
  END q_o[178]
  PIN q_o[179]
    DIRECTION OUTPUT ;
    USE SIGNAL ;
    ANTENNADIFFAREA 0.708600 ;
    PORT
      LAYER Metal3 ;
        RECT 0.000 101.020 0.400 101.420 ;
    END
  END q_o[179]
  PIN q_o[17]
    DIRECTION OUTPUT ;
    USE SIGNAL ;
    ANTENNADIFFAREA 0.708600 ;
    PORT
      LAYER Metal2 ;
        RECT 140.440 234.300 140.840 234.700 ;
    END
  END q_o[17]
  PIN q_o[180]
    DIRECTION OUTPUT ;
    USE SIGNAL ;
    ANTENNADIFFAREA 0.708600 ;
    PORT
      LAYER Metal3 ;
        RECT 215.580 187.540 215.980 187.940 ;
    END
  END q_o[180]
  PIN q_o[181]
    DIRECTION OUTPUT ;
    USE SIGNAL ;
    ANTENNADIFFAREA 0.708600 ;
    PORT
      LAYER Metal2 ;
        RECT 205.720 0.000 206.120 0.400 ;
    END
  END q_o[181]
  PIN q_o[182]
    DIRECTION OUTPUT ;
    USE SIGNAL ;
    ANTENNADIFFAREA 0.708600 ;
    PORT
      LAYER Metal3 ;
        RECT 215.580 53.980 215.980 54.380 ;
    END
  END q_o[182]
  PIN q_o[183]
    DIRECTION OUTPUT ;
    USE SIGNAL ;
    ANTENNADIFFAREA 0.708600 ;
    PORT
      LAYER Metal3 ;
        RECT 0.000 115.300 0.400 115.700 ;
    END
  END q_o[183]
  PIN q_o[184]
    DIRECTION OUTPUT ;
    USE SIGNAL ;
    ANTENNADIFFAREA 0.708600 ;
    PORT
      LAYER Metal2 ;
        RECT 76.120 234.300 76.520 234.700 ;
    END
  END q_o[184]
  PIN q_o[185]
    DIRECTION OUTPUT ;
    USE SIGNAL ;
    ANTENNADIFFAREA 0.708600 ;
    PORT
      LAYER Metal2 ;
        RECT 110.680 0.000 111.080 0.400 ;
    END
  END q_o[185]
  PIN q_o[186]
    DIRECTION OUTPUT ;
    USE SIGNAL ;
    ANTENNADIFFAREA 0.708600 ;
    PORT
      LAYER Metal3 ;
        RECT 0.000 43.060 0.400 43.460 ;
    END
  END q_o[186]
  PIN q_o[187]
    DIRECTION OUTPUT ;
    USE SIGNAL ;
    ANTENNADIFFAREA 0.708600 ;
    PORT
      LAYER Metal3 ;
        RECT 0.000 25.420 0.400 25.820 ;
    END
  END q_o[187]
  PIN q_o[188]
    DIRECTION OUTPUT ;
    USE SIGNAL ;
    ANTENNADIFFAREA 0.708600 ;
    PORT
      LAYER Metal2 ;
        RECT 109.720 0.000 110.120 0.400 ;
    END
  END q_o[188]
  PIN q_o[189]
    DIRECTION OUTPUT ;
    USE SIGNAL ;
    ANTENNADIFFAREA 0.708600 ;
    PORT
      LAYER Metal2 ;
        RECT 128.920 0.000 129.320 0.400 ;
    END
  END q_o[189]
  PIN q_o[18]
    DIRECTION OUTPUT ;
    USE SIGNAL ;
    ANTENNADIFFAREA 0.708600 ;
    PORT
      LAYER Metal2 ;
        RECT 63.640 0.000 64.040 0.400 ;
    END
  END q_o[18]
  PIN q_o[190]
    DIRECTION OUTPUT ;
    USE SIGNAL ;
    ANTENNADIFFAREA 0.708600 ;
    PORT
      LAYER Metal3 ;
        RECT 0.000 129.580 0.400 129.980 ;
    END
  END q_o[190]
  PIN q_o[191]
    DIRECTION OUTPUT ;
    USE SIGNAL ;
    ANTENNADIFFAREA 0.708600 ;
    PORT
      LAYER Metal3 ;
        RECT 215.580 101.020 215.980 101.420 ;
    END
  END q_o[191]
  PIN q_o[192]
    DIRECTION OUTPUT ;
    USE SIGNAL ;
    ANTENNADIFFAREA 0.708600 ;
    PORT
      LAYER Metal3 ;
        RECT 0.000 110.260 0.400 110.660 ;
    END
  END q_o[192]
  PIN q_o[193]
    DIRECTION OUTPUT ;
    USE SIGNAL ;
    ANTENNADIFFAREA 0.708600 ;
    PORT
      LAYER Metal3 ;
        RECT 0.000 107.740 0.400 108.140 ;
    END
  END q_o[193]
  PIN q_o[194]
    DIRECTION OUTPUT ;
    USE SIGNAL ;
    ANTENNADIFFAREA 0.708600 ;
    PORT
      LAYER Metal2 ;
        RECT 136.600 234.300 137.000 234.700 ;
    END
  END q_o[194]
  PIN q_o[195]
    DIRECTION OUTPUT ;
    USE SIGNAL ;
    ANTENNADIFFAREA 0.708600 ;
    PORT
      LAYER Metal2 ;
        RECT 144.280 0.000 144.680 0.400 ;
    END
  END q_o[195]
  PIN q_o[196]
    DIRECTION OUTPUT ;
    USE SIGNAL ;
    ANTENNADIFFAREA 0.708600 ;
    PORT
      LAYER Metal3 ;
        RECT 0.000 121.180 0.400 121.580 ;
    END
  END q_o[196]
  PIN q_o[197]
    DIRECTION OUTPUT ;
    USE SIGNAL ;
    ANTENNADIFFAREA 0.708600 ;
    PORT
      LAYER Metal3 ;
        RECT 215.580 77.500 215.980 77.900 ;
    END
  END q_o[197]
  PIN q_o[198]
    DIRECTION OUTPUT ;
    USE SIGNAL ;
    ANTENNADIFFAREA 0.708600 ;
    PORT
      LAYER Metal3 ;
        RECT 0.000 166.540 0.400 166.940 ;
    END
  END q_o[198]
  PIN q_o[199]
    DIRECTION OUTPUT ;
    USE SIGNAL ;
    ANTENNADIFFAREA 0.708600 ;
    PORT
      LAYER Metal3 ;
        RECT 0.000 111.940 0.400 112.340 ;
    END
  END q_o[199]
  PIN q_o[19]
    DIRECTION OUTPUT ;
    USE SIGNAL ;
    ANTENNADIFFAREA 0.708600 ;
    PORT
      LAYER Metal3 ;
        RECT 0.000 130.420 0.400 130.820 ;
    END
  END q_o[19]
  PIN q_o[1]
    DIRECTION OUTPUT ;
    USE SIGNAL ;
    ANTENNADIFFAREA 0.708600 ;
    PORT
      LAYER Metal3 ;
        RECT 215.580 200.140 215.980 200.540 ;
    END
  END q_o[1]
  PIN q_o[200]
    DIRECTION OUTPUT ;
    USE SIGNAL ;
    ANTENNADIFFAREA 0.708600 ;
    PORT
      LAYER Metal3 ;
        RECT 0.000 151.420 0.400 151.820 ;
    END
  END q_o[200]
  PIN q_o[201]
    DIRECTION OUTPUT ;
    USE SIGNAL ;
    ANTENNADIFFAREA 0.708600 ;
    PORT
      LAYER Metal3 ;
        RECT 0.000 117.820 0.400 118.220 ;
    END
  END q_o[201]
  PIN q_o[202]
    DIRECTION OUTPUT ;
    USE SIGNAL ;
    ANTENNADIFFAREA 0.708600 ;
    PORT
      LAYER Metal3 ;
        RECT 0.000 142.180 0.400 142.580 ;
    END
  END q_o[202]
  PIN q_o[203]
    DIRECTION OUTPUT ;
    USE SIGNAL ;
    ANTENNADIFFAREA 0.708600 ;
    PORT
      LAYER Metal3 ;
        RECT 0.000 93.460 0.400 93.860 ;
    END
  END q_o[203]
  PIN q_o[204]
    DIRECTION OUTPUT ;
    USE SIGNAL ;
    ANTENNADIFFAREA 0.708600 ;
    PORT
      LAYER Metal2 ;
        RECT 73.240 234.300 73.640 234.700 ;
    END
  END q_o[204]
  PIN q_o[205]
    DIRECTION OUTPUT ;
    USE SIGNAL ;
    ANTENNADIFFAREA 0.708600 ;
    PORT
      LAYER Metal3 ;
        RECT 0.000 183.340 0.400 183.740 ;
    END
  END q_o[205]
  PIN q_o[206]
    DIRECTION OUTPUT ;
    USE SIGNAL ;
    ANTENNADIFFAREA 0.708600 ;
    PORT
      LAYER Metal3 ;
        RECT 0.000 141.340 0.400 141.740 ;
    END
  END q_o[206]
  PIN q_o[207]
    DIRECTION OUTPUT ;
    USE SIGNAL ;
    ANTENNADIFFAREA 0.708600 ;
    PORT
      LAYER Metal3 ;
        RECT 0.000 60.700 0.400 61.100 ;
    END
  END q_o[207]
  PIN q_o[208]
    DIRECTION OUTPUT ;
    USE SIGNAL ;
    ANTENNADIFFAREA 0.708600 ;
    PORT
      LAYER Metal3 ;
        RECT 0.000 185.020 0.400 185.420 ;
    END
  END q_o[208]
  PIN q_o[209]
    DIRECTION OUTPUT ;
    USE SIGNAL ;
    ANTENNADIFFAREA 0.708600 ;
    PORT
      LAYER Metal2 ;
        RECT 94.360 0.000 94.760 0.400 ;
    END
  END q_o[209]
  PIN q_o[20]
    DIRECTION OUTPUT ;
    USE SIGNAL ;
    ANTENNADIFFAREA 0.708600 ;
    PORT
      LAYER Metal3 ;
        RECT 0.000 169.900 0.400 170.300 ;
    END
  END q_o[20]
  PIN q_o[210]
    DIRECTION OUTPUT ;
    USE SIGNAL ;
    ANTENNADIFFAREA 0.708600 ;
    PORT
      LAYER Metal2 ;
        RECT 118.360 234.300 118.760 234.700 ;
    END
  END q_o[210]
  PIN q_o[211]
    DIRECTION OUTPUT ;
    USE SIGNAL ;
    ANTENNADIFFAREA 0.708600 ;
    PORT
      LAYER Metal3 ;
        RECT 215.580 190.060 215.980 190.460 ;
    END
  END q_o[211]
  PIN q_o[212]
    DIRECTION OUTPUT ;
    USE SIGNAL ;
    ANTENNADIFFAREA 0.708600 ;
    PORT
      LAYER Metal3 ;
        RECT 215.580 116.140 215.980 116.540 ;
    END
  END q_o[212]
  PIN q_o[213]
    DIRECTION OUTPUT ;
    USE SIGNAL ;
    ANTENNADIFFAREA 0.708600 ;
    PORT
      LAYER Metal3 ;
        RECT 215.580 121.180 215.980 121.580 ;
    END
  END q_o[213]
  PIN q_o[214]
    DIRECTION OUTPUT ;
    USE SIGNAL ;
    ANTENNADIFFAREA 0.708600 ;
    PORT
      LAYER Metal2 ;
        RECT 105.880 234.300 106.280 234.700 ;
    END
  END q_o[214]
  PIN q_o[215]
    DIRECTION OUTPUT ;
    USE SIGNAL ;
    ANTENNADIFFAREA 0.708600 ;
    PORT
      LAYER Metal3 ;
        RECT 215.580 207.700 215.980 208.100 ;
    END
  END q_o[215]
  PIN q_o[216]
    DIRECTION OUTPUT ;
    USE SIGNAL ;
    ANTENNADIFFAREA 0.708600 ;
    PORT
      LAYER Metal3 ;
        RECT 215.580 90.100 215.980 90.500 ;
    END
  END q_o[216]
  PIN q_o[217]
    DIRECTION OUTPUT ;
    USE SIGNAL ;
    ANTENNADIFFAREA 0.708600 ;
    PORT
      LAYER Metal2 ;
        RECT 114.520 234.300 114.920 234.700 ;
    END
  END q_o[217]
  PIN q_o[218]
    DIRECTION OUTPUT ;
    USE SIGNAL ;
    ANTENNADIFFAREA 0.708600 ;
    PORT
      LAYER Metal2 ;
        RECT 119.320 0.000 119.720 0.400 ;
    END
  END q_o[218]
  PIN q_o[219]
    DIRECTION OUTPUT ;
    USE SIGNAL ;
    ANTENNADIFFAREA 0.708600 ;
    PORT
      LAYER Metal2 ;
        RECT 135.640 0.000 136.040 0.400 ;
    END
  END q_o[219]
  PIN q_o[21]
    DIRECTION OUTPUT ;
    USE SIGNAL ;
    ANTENNADIFFAREA 0.708600 ;
    PORT
      LAYER Metal2 ;
        RECT 139.480 234.300 139.880 234.700 ;
    END
  END q_o[21]
  PIN q_o[220]
    DIRECTION OUTPUT ;
    USE SIGNAL ;
    ANTENNADIFFAREA 0.708600 ;
    PORT
      LAYER Metal2 ;
        RECT 143.320 234.300 143.720 234.700 ;
    END
  END q_o[220]
  PIN q_o[221]
    DIRECTION OUTPUT ;
    USE SIGNAL ;
    ANTENNADIFFAREA 0.708600 ;
    PORT
      LAYER Metal2 ;
        RECT 85.720 0.000 86.120 0.400 ;
    END
  END q_o[221]
  PIN q_o[222]
    DIRECTION OUTPUT ;
    USE SIGNAL ;
    ANTENNADIFFAREA 0.708600 ;
    PORT
      LAYER Metal3 ;
        RECT 0.000 165.700 0.400 166.100 ;
    END
  END q_o[222]
  PIN q_o[223]
    DIRECTION OUTPUT ;
    USE SIGNAL ;
    ANTENNADIFFAREA 0.708600 ;
    PORT
      LAYER Metal3 ;
        RECT 215.580 59.860 215.980 60.260 ;
    END
  END q_o[223]
  PIN q_o[224]
    DIRECTION OUTPUT ;
    USE SIGNAL ;
    ANTENNADIFFAREA 0.708600 ;
    PORT
      LAYER Metal3 ;
        RECT 0.000 143.020 0.400 143.420 ;
    END
  END q_o[224]
  PIN q_o[225]
    DIRECTION OUTPUT ;
    USE SIGNAL ;
    ANTENNADIFFAREA 0.708600 ;
    PORT
      LAYER Metal3 ;
        RECT 215.580 194.260 215.980 194.660 ;
    END
  END q_o[225]
  PIN q_o[226]
    DIRECTION OUTPUT ;
    USE SIGNAL ;
    ANTENNADIFFAREA 0.708600 ;
    PORT
      LAYER Metal3 ;
        RECT 215.580 137.980 215.980 138.380 ;
    END
  END q_o[226]
  PIN q_o[227]
    DIRECTION OUTPUT ;
    USE SIGNAL ;
    ANTENNADIFFAREA 0.708600 ;
    PORT
      LAYER Metal2 ;
        RECT 67.480 0.000 67.880 0.400 ;
    END
  END q_o[227]
  PIN q_o[228]
    DIRECTION OUTPUT ;
    USE SIGNAL ;
    ANTENNADIFFAREA 0.708600 ;
    PORT
      LAYER Metal2 ;
        RECT 124.120 0.000 124.520 0.400 ;
    END
  END q_o[228]
  PIN q_o[229]
    DIRECTION OUTPUT ;
    USE SIGNAL ;
    ANTENNADIFFAREA 0.708600 ;
    PORT
      LAYER Metal2 ;
        RECT 97.240 234.300 97.640 234.700 ;
    END
  END q_o[229]
  PIN q_o[22]
    DIRECTION OUTPUT ;
    USE SIGNAL ;
    ANTENNADIFFAREA 0.708600 ;
    PORT
      LAYER Metal2 ;
        RECT 116.440 0.000 116.840 0.400 ;
    END
  END q_o[22]
  PIN q_o[230]
    DIRECTION OUTPUT ;
    USE SIGNAL ;
    ANTENNADIFFAREA 0.708600 ;
    PORT
      LAYER Metal3 ;
        RECT 215.580 67.420 215.980 67.820 ;
    END
  END q_o[230]
  PIN q_o[231]
    DIRECTION OUTPUT ;
    USE SIGNAL ;
    ANTENNADIFFAREA 0.708600 ;
    PORT
      LAYER Metal3 ;
        RECT 0.000 152.260 0.400 152.660 ;
    END
  END q_o[231]
  PIN q_o[232]
    DIRECTION OUTPUT ;
    USE SIGNAL ;
    ANTENNADIFFAREA 0.708600 ;
    PORT
      LAYER Metal2 ;
        RECT 194.200 0.000 194.600 0.400 ;
    END
  END q_o[232]
  PIN q_o[233]
    DIRECTION OUTPUT ;
    USE SIGNAL ;
    ANTENNADIFFAREA 0.708600 ;
    PORT
      LAYER Metal2 ;
        RECT 133.720 234.300 134.120 234.700 ;
    END
  END q_o[233]
  PIN q_o[234]
    DIRECTION OUTPUT ;
    USE SIGNAL ;
    ANTENNADIFFAREA 0.708600 ;
    PORT
      LAYER Metal3 ;
        RECT 0.000 138.820 0.400 139.220 ;
    END
  END q_o[234]
  PIN q_o[235]
    DIRECTION OUTPUT ;
    USE SIGNAL ;
    ANTENNADIFFAREA 0.708600 ;
    PORT
      LAYER Metal2 ;
        RECT 92.440 234.300 92.840 234.700 ;
    END
  END q_o[235]
  PIN q_o[236]
    DIRECTION OUTPUT ;
    USE SIGNAL ;
    ANTENNADIFFAREA 0.708600 ;
    PORT
      LAYER Metal2 ;
        RECT 114.520 0.000 114.920 0.400 ;
    END
  END q_o[236]
  PIN q_o[237]
    DIRECTION OUTPUT ;
    USE SIGNAL ;
    ANTENNADIFFAREA 0.708600 ;
    PORT
      LAYER Metal2 ;
        RECT 202.840 0.000 203.240 0.400 ;
    END
  END q_o[237]
  PIN q_o[238]
    DIRECTION OUTPUT ;
    USE SIGNAL ;
    ANTENNADIFFAREA 0.708600 ;
    PORT
      LAYER Metal3 ;
        RECT 215.580 83.380 215.980 83.780 ;
    END
  END q_o[238]
  PIN q_o[239]
    DIRECTION OUTPUT ;
    USE SIGNAL ;
    ANTENNADIFFAREA 0.708600 ;
    PORT
      LAYER Metal3 ;
        RECT 215.580 177.460 215.980 177.860 ;
    END
  END q_o[239]
  PIN q_o[23]
    DIRECTION OUTPUT ;
    USE SIGNAL ;
    ANTENNADIFFAREA 0.708600 ;
    PORT
      LAYER Metal2 ;
        RECT 199.960 0.000 200.360 0.400 ;
    END
  END q_o[23]
  PIN q_o[240]
    DIRECTION OUTPUT ;
    USE SIGNAL ;
    ANTENNADIFFAREA 0.708600 ;
    PORT
      LAYER Metal2 ;
        RECT 132.760 0.000 133.160 0.400 ;
    END
  END q_o[240]
  PIN q_o[241]
    DIRECTION OUTPUT ;
    USE SIGNAL ;
    ANTENNADIFFAREA 0.708600 ;
    PORT
      LAYER Metal2 ;
        RECT 6.040 234.300 6.440 234.700 ;
    END
  END q_o[241]
  PIN q_o[242]
    DIRECTION OUTPUT ;
    USE SIGNAL ;
    ANTENNADIFFAREA 0.708600 ;
    PORT
      LAYER Metal3 ;
        RECT 215.580 120.340 215.980 120.740 ;
    END
  END q_o[242]
  PIN q_o[243]
    DIRECTION OUTPUT ;
    USE SIGNAL ;
    ANTENNADIFFAREA 0.708600 ;
    PORT
      LAYER Metal3 ;
        RECT 215.580 192.580 215.980 192.980 ;
    END
  END q_o[243]
  PIN q_o[244]
    DIRECTION OUTPUT ;
    USE SIGNAL ;
    ANTENNADIFFAREA 0.708600 ;
    PORT
      LAYER Metal3 ;
        RECT 215.580 79.180 215.980 79.580 ;
    END
  END q_o[244]
  PIN q_o[245]
    DIRECTION OUTPUT ;
    USE SIGNAL ;
    ANTENNADIFFAREA 0.708600 ;
    PORT
      LAYER Metal3 ;
        RECT 215.580 64.060 215.980 64.460 ;
    END
  END q_o[245]
  PIN q_o[246]
    DIRECTION OUTPUT ;
    USE SIGNAL ;
    ANTENNADIFFAREA 0.708600 ;
    PORT
      LAYER Metal2 ;
        RECT 20.440 234.300 20.840 234.700 ;
    END
  END q_o[246]
  PIN q_o[247]
    DIRECTION OUTPUT ;
    USE SIGNAL ;
    ANTENNADIFFAREA 0.708600 ;
    PORT
      LAYER Metal2 ;
        RECT 132.760 234.300 133.160 234.700 ;
    END
  END q_o[247]
  PIN q_o[248]
    DIRECTION OUTPUT ;
    USE SIGNAL ;
    ANTENNADIFFAREA 0.708600 ;
    PORT
      LAYER Metal3 ;
        RECT 0.000 45.580 0.400 45.980 ;
    END
  END q_o[248]
  PIN q_o[249]
    DIRECTION OUTPUT ;
    USE SIGNAL ;
    ANTENNADIFFAREA 0.708600 ;
    PORT
      LAYER Metal2 ;
        RECT 134.680 0.000 135.080 0.400 ;
    END
  END q_o[249]
  PIN q_o[24]
    DIRECTION OUTPUT ;
    USE SIGNAL ;
    ANTENNADIFFAREA 0.708600 ;
    PORT
      LAYER Metal3 ;
        RECT 215.580 204.340 215.980 204.740 ;
    END
  END q_o[24]
  PIN q_o[250]
    DIRECTION OUTPUT ;
    USE SIGNAL ;
    ANTENNADIFFAREA 0.708600 ;
    PORT
      LAYER Metal3 ;
        RECT 215.580 210.220 215.980 210.620 ;
    END
  END q_o[250]
  PIN q_o[251]
    DIRECTION OUTPUT ;
    USE SIGNAL ;
    ANTENNADIFFAREA 0.708600 ;
    PORT
      LAYER Metal2 ;
        RECT 130.840 234.300 131.240 234.700 ;
    END
  END q_o[251]
  PIN q_o[252]
    DIRECTION OUTPUT ;
    USE SIGNAL ;
    ANTENNADIFFAREA 0.708600 ;
    PORT
      LAYER Metal2 ;
        RECT 106.840 234.300 107.240 234.700 ;
    END
  END q_o[252]
  PIN q_o[253]
    DIRECTION OUTPUT ;
    USE SIGNAL ;
    ANTENNADIFFAREA 0.708600 ;
    PORT
      LAYER Metal2 ;
        RECT 149.080 0.000 149.480 0.400 ;
    END
  END q_o[253]
  PIN q_o[254]
    DIRECTION OUTPUT ;
    USE SIGNAL ;
    ANTENNADIFFAREA 0.708600 ;
    PORT
      LAYER Metal3 ;
        RECT 215.580 55.660 215.980 56.060 ;
    END
  END q_o[254]
  PIN q_o[255]
    DIRECTION OUTPUT ;
    USE SIGNAL ;
    ANTENNADIFFAREA 0.708600 ;
    PORT
      LAYER Metal3 ;
        RECT 215.580 176.620 215.980 177.020 ;
    END
  END q_o[255]
  PIN q_o[25]
    DIRECTION OUTPUT ;
    USE SIGNAL ;
    ANTENNADIFFAREA 0.708600 ;
    PORT
      LAYER Metal3 ;
        RECT 215.580 81.700 215.980 82.100 ;
    END
  END q_o[25]
  PIN q_o[26]
    DIRECTION OUTPUT ;
    USE SIGNAL ;
    ANTENNADIFFAREA 0.708600 ;
    PORT
      LAYER Metal2 ;
        RECT 107.800 234.300 108.200 234.700 ;
    END
  END q_o[26]
  PIN q_o[27]
    DIRECTION OUTPUT ;
    USE SIGNAL ;
    ANTENNADIFFAREA 0.708600 ;
    PORT
      LAYER Metal3 ;
        RECT 0.000 59.020 0.400 59.420 ;
    END
  END q_o[27]
  PIN q_o[28]
    DIRECTION OUTPUT ;
    USE SIGNAL ;
    ANTENNADIFFAREA 0.708600 ;
    PORT
      LAYER Metal2 ;
        RECT 90.520 234.300 90.920 234.700 ;
    END
  END q_o[28]
  PIN q_o[29]
    DIRECTION OUTPUT ;
    USE SIGNAL ;
    ANTENNADIFFAREA 0.708600 ;
    PORT
      LAYER Metal3 ;
        RECT 0.000 161.500 0.400 161.900 ;
    END
  END q_o[29]
  PIN q_o[2]
    DIRECTION OUTPUT ;
    USE SIGNAL ;
    ANTENNADIFFAREA 0.708600 ;
    PORT
      LAYER Metal2 ;
        RECT 87.640 234.300 88.040 234.700 ;
    END
  END q_o[2]
  PIN q_o[30]
    DIRECTION OUTPUT ;
    USE SIGNAL ;
    ANTENNADIFFAREA 0.708600 ;
    PORT
      LAYER Metal3 ;
        RECT 215.580 136.300 215.980 136.700 ;
    END
  END q_o[30]
  PIN q_o[31]
    DIRECTION OUTPUT ;
    USE SIGNAL ;
    ANTENNADIFFAREA 0.708600 ;
    PORT
      LAYER Metal2 ;
        RECT 122.200 234.300 122.600 234.700 ;
    END
  END q_o[31]
  PIN q_o[32]
    DIRECTION OUTPUT ;
    USE SIGNAL ;
    ANTENNADIFFAREA 0.708600 ;
    PORT
      LAYER Metal3 ;
        RECT 215.580 85.900 215.980 86.300 ;
    END
  END q_o[32]
  PIN q_o[33]
    DIRECTION OUTPUT ;
    USE SIGNAL ;
    ANTENNADIFFAREA 0.708600 ;
    PORT
      LAYER Metal2 ;
        RECT 75.160 0.000 75.560 0.400 ;
    END
  END q_o[33]
  PIN q_o[34]
    DIRECTION OUTPUT ;
    USE SIGNAL ;
    ANTENNADIFFAREA 0.708600 ;
    PORT
      LAYER Metal3 ;
        RECT 215.580 130.420 215.980 130.820 ;
    END
  END q_o[34]
  PIN q_o[35]
    DIRECTION OUTPUT ;
    USE SIGNAL ;
    ANTENNADIFFAREA 0.708600 ;
    PORT
      LAYER Metal2 ;
        RECT 60.760 0.000 61.160 0.400 ;
    END
  END q_o[35]
  PIN q_o[36]
    DIRECTION OUTPUT ;
    USE SIGNAL ;
    ANTENNADIFFAREA 0.708600 ;
    PORT
      LAYER Metal3 ;
        RECT 0.000 149.740 0.400 150.140 ;
    END
  END q_o[36]
  PIN q_o[37]
    DIRECTION OUTPUT ;
    USE SIGNAL ;
    ANTENNADIFFAREA 0.708600 ;
    PORT
      LAYER Metal2 ;
        RECT 100.120 234.300 100.520 234.700 ;
    END
  END q_o[37]
  PIN q_o[38]
    DIRECTION OUTPUT ;
    USE SIGNAL ;
    ANTENNADIFFAREA 0.708600 ;
    PORT
      LAYER Metal2 ;
        RECT 66.520 0.000 66.920 0.400 ;
    END
  END q_o[38]
  PIN q_o[39]
    DIRECTION OUTPUT ;
    USE SIGNAL ;
    ANTENNADIFFAREA 0.708600 ;
    PORT
      LAYER Metal3 ;
        RECT 215.580 173.260 215.980 173.660 ;
    END
  END q_o[39]
  PIN q_o[3]
    DIRECTION OUTPUT ;
    USE SIGNAL ;
    ANTENNADIFFAREA 0.708600 ;
    PORT
      LAYER Metal2 ;
        RECT 14.680 234.300 15.080 234.700 ;
    END
  END q_o[3]
  PIN q_o[40]
    DIRECTION OUTPUT ;
    USE SIGNAL ;
    ANTENNADIFFAREA 0.708600 ;
    PORT
      LAYER Metal3 ;
        RECT 215.580 54.820 215.980 55.220 ;
    END
  END q_o[40]
  PIN q_o[41]
    DIRECTION OUTPUT ;
    USE SIGNAL ;
    ANTENNADIFFAREA 0.708600 ;
    PORT
      LAYER Metal2 ;
        RECT 113.560 234.300 113.960 234.700 ;
    END
  END q_o[41]
  PIN q_o[42]
    DIRECTION OUTPUT ;
    USE SIGNAL ;
    ANTENNADIFFAREA 0.708600 ;
    PORT
      LAYER Metal2 ;
        RECT 141.400 234.300 141.800 234.700 ;
    END
  END q_o[42]
  PIN q_o[43]
    DIRECTION OUTPUT ;
    USE SIGNAL ;
    ANTENNADIFFAREA 0.708600 ;
    PORT
      LAYER Metal2 ;
        RECT 91.480 0.000 91.880 0.400 ;
    END
  END q_o[43]
  PIN q_o[44]
    DIRECTION OUTPUT ;
    USE SIGNAL ;
    ANTENNADIFFAREA 0.708600 ;
    PORT
      LAYER Metal3 ;
        RECT 215.580 181.660 215.980 182.060 ;
    END
  END q_o[44]
  PIN q_o[45]
    DIRECTION OUTPUT ;
    USE SIGNAL ;
    ANTENNADIFFAREA 0.708600 ;
    PORT
      LAYER Metal3 ;
        RECT 0.000 28.780 0.400 29.180 ;
    END
  END q_o[45]
  PIN q_o[46]
    DIRECTION OUTPUT ;
    USE SIGNAL ;
    ANTENNADIFFAREA 0.708600 ;
    PORT
      LAYER Metal3 ;
        RECT 215.580 174.100 215.980 174.500 ;
    END
  END q_o[46]
  PIN q_o[47]
    DIRECTION OUTPUT ;
    USE SIGNAL ;
    ANTENNADIFFAREA 0.708600 ;
    PORT
      LAYER Metal3 ;
        RECT 0.000 159.820 0.400 160.220 ;
    END
  END q_o[47]
  PIN q_o[48]
    DIRECTION OUTPUT ;
    USE SIGNAL ;
    ANTENNADIFFAREA 0.708600 ;
    PORT
      LAYER Metal2 ;
        RECT 92.440 0.000 92.840 0.400 ;
    END
  END q_o[48]
  PIN q_o[49]
    DIRECTION OUTPUT ;
    USE SIGNAL ;
    ANTENNADIFFAREA 0.708600 ;
    PORT
      LAYER Metal3 ;
        RECT 215.580 133.780 215.980 134.180 ;
    END
  END q_o[49]
  PIN q_o[4]
    DIRECTION OUTPUT ;
    USE SIGNAL ;
    ANTENNADIFFAREA 0.708600 ;
    PORT
      LAYER Metal2 ;
        RECT 99.160 234.300 99.560 234.700 ;
    END
  END q_o[4]
  PIN q_o[50]
    DIRECTION OUTPUT ;
    USE SIGNAL ;
    ANTENNADIFFAREA 0.708600 ;
    PORT
      LAYER Metal3 ;
        RECT 215.580 182.500 215.980 182.900 ;
    END
  END q_o[50]
  PIN q_o[51]
    DIRECTION OUTPUT ;
    USE SIGNAL ;
    ANTENNADIFFAREA 0.708600 ;
    PORT
      LAYER Metal2 ;
        RECT 65.560 234.300 65.960 234.700 ;
    END
  END q_o[51]
  PIN q_o[52]
    DIRECTION OUTPUT ;
    USE SIGNAL ;
    ANTENNADIFFAREA 0.708600 ;
    PORT
      LAYER Metal3 ;
        RECT 215.580 190.900 215.980 191.300 ;
    END
  END q_o[52]
  PIN q_o[53]
    DIRECTION OUTPUT ;
    USE SIGNAL ;
    ANTENNADIFFAREA 0.708600 ;
    PORT
      LAYER Metal3 ;
        RECT 0.000 168.220 0.400 168.620 ;
    END
  END q_o[53]
  PIN q_o[54]
    DIRECTION OUTPUT ;
    USE SIGNAL ;
    ANTENNADIFFAREA 0.708600 ;
    PORT
      LAYER Metal3 ;
        RECT 0.000 51.460 0.400 51.860 ;
    END
  END q_o[54]
  PIN q_o[55]
    DIRECTION OUTPUT ;
    USE SIGNAL ;
    ANTENNADIFFAREA 0.708600 ;
    PORT
      LAYER Metal2 ;
        RECT 206.680 0.000 207.080 0.400 ;
    END
  END q_o[55]
  PIN q_o[56]
    DIRECTION OUTPUT ;
    USE SIGNAL ;
    ANTENNADIFFAREA 0.708600 ;
    PORT
      LAYER Metal2 ;
        RECT 125.080 234.300 125.480 234.700 ;
    END
  END q_o[56]
  PIN q_o[57]
    DIRECTION OUTPUT ;
    USE SIGNAL ;
    ANTENNADIFFAREA 0.708600 ;
    PORT
      LAYER Metal3 ;
        RECT 215.580 95.980 215.980 96.380 ;
    END
  END q_o[57]
  PIN q_o[58]
    DIRECTION OUTPUT ;
    USE SIGNAL ;
    ANTENNADIFFAREA 0.708600 ;
    PORT
      LAYER Metal3 ;
        RECT 0.000 29.620 0.400 30.020 ;
    END
  END q_o[58]
  PIN q_o[59]
    DIRECTION OUTPUT ;
    USE SIGNAL ;
    ANTENNADIFFAREA 0.708600 ;
    PORT
      LAYER Metal3 ;
        RECT 215.580 125.380 215.980 125.780 ;
    END
  END q_o[59]
  PIN q_o[5]
    DIRECTION OUTPUT ;
    USE SIGNAL ;
    ANTENNADIFFAREA 0.708600 ;
    PORT
      LAYER Metal3 ;
        RECT 215.580 64.900 215.980 65.300 ;
    END
  END q_o[5]
  PIN q_o[60]
    DIRECTION OUTPUT ;
    USE SIGNAL ;
    ANTENNADIFFAREA 0.708600 ;
    PORT
      LAYER Metal3 ;
        RECT 215.580 198.460 215.980 198.860 ;
    END
  END q_o[60]
  PIN q_o[61]
    DIRECTION OUTPUT ;
    USE SIGNAL ;
    ANTENNADIFFAREA 0.708600 ;
    PORT
      LAYER Metal3 ;
        RECT 215.580 80.860 215.980 81.260 ;
    END
  END q_o[61]
  PIN q_o[62]
    DIRECTION OUTPUT ;
    USE SIGNAL ;
    ANTENNADIFFAREA 0.708600 ;
    PORT
      LAYER Metal3 ;
        RECT 215.580 93.460 215.980 93.860 ;
    END
  END q_o[62]
  PIN q_o[63]
    DIRECTION OUTPUT ;
    USE SIGNAL ;
    ANTENNADIFFAREA 0.708600 ;
    PORT
      LAYER Metal2 ;
        RECT 115.480 0.000 115.880 0.400 ;
    END
  END q_o[63]
  PIN q_o[64]
    DIRECTION OUTPUT ;
    USE SIGNAL ;
    ANTENNADIFFAREA 0.708600 ;
    PORT
      LAYER Metal2 ;
        RECT 127.000 0.000 127.400 0.400 ;
    END
  END q_o[64]
  PIN q_o[65]
    DIRECTION OUTPUT ;
    USE SIGNAL ;
    ANTENNADIFFAREA 0.708600 ;
    PORT
      LAYER Metal3 ;
        RECT 215.580 129.580 215.980 129.980 ;
    END
  END q_o[65]
  PIN q_o[66]
    DIRECTION OUTPUT ;
    USE SIGNAL ;
    ANTENNADIFFAREA 0.708600 ;
    PORT
      LAYER Metal2 ;
        RECT 131.800 234.300 132.200 234.700 ;
    END
  END q_o[66]
  PIN q_o[67]
    DIRECTION OUTPUT ;
    USE SIGNAL ;
    ANTENNADIFFAREA 0.708600 ;
    PORT
      LAYER Metal3 ;
        RECT 0.000 34.660 0.400 35.060 ;
    END
  END q_o[67]
  PIN q_o[68]
    DIRECTION OUTPUT ;
    USE SIGNAL ;
    ANTENNADIFFAREA 0.708600 ;
    PORT
      LAYER Metal2 ;
        RECT 74.200 234.300 74.600 234.700 ;
    END
  END q_o[68]
  PIN q_o[69]
    DIRECTION OUTPUT ;
    USE SIGNAL ;
    ANTENNADIFFAREA 0.708600 ;
    PORT
      LAYER Metal2 ;
        RECT 17.560 234.300 17.960 234.700 ;
    END
  END q_o[69]
  PIN q_o[6]
    DIRECTION OUTPUT ;
    USE SIGNAL ;
    ANTENNADIFFAREA 0.708600 ;
    PORT
      LAYER Metal3 ;
        RECT 215.580 92.620 215.980 93.020 ;
    END
  END q_o[6]
  PIN q_o[70]
    DIRECTION OUTPUT ;
    USE SIGNAL ;
    ANTENNADIFFAREA 0.708600 ;
    PORT
      LAYER Metal2 ;
        RECT 89.560 0.000 89.960 0.400 ;
    END
  END q_o[70]
  PIN q_o[71]
    DIRECTION OUTPUT ;
    USE SIGNAL ;
    ANTENNADIFFAREA 0.708600 ;
    PORT
      LAYER Metal3 ;
        RECT 0.000 91.780 0.400 92.180 ;
    END
  END q_o[71]
  PIN q_o[72]
    DIRECTION OUTPUT ;
    USE SIGNAL ;
    ANTENNADIFFAREA 0.708600 ;
    PORT
      LAYER Metal2 ;
        RECT 102.040 234.300 102.440 234.700 ;
    END
  END q_o[72]
  PIN q_o[73]
    DIRECTION OUTPUT ;
    USE SIGNAL ;
    ANTENNADIFFAREA 0.708600 ;
    PORT
      LAYER Metal3 ;
        RECT 215.580 172.420 215.980 172.820 ;
    END
  END q_o[73]
  PIN q_o[74]
    DIRECTION OUTPUT ;
    USE SIGNAL ;
    ANTENNADIFFAREA 0.708600 ;
    PORT
      LAYER Metal3 ;
        RECT 215.580 84.220 215.980 84.620 ;
    END
  END q_o[74]
  PIN q_o[75]
    DIRECTION OUTPUT ;
    USE SIGNAL ;
    ANTENNADIFFAREA 0.708600 ;
    PORT
      LAYER Metal2 ;
        RECT 112.600 234.300 113.000 234.700 ;
    END
  END q_o[75]
  PIN q_o[76]
    DIRECTION OUTPUT ;
    USE SIGNAL ;
    ANTENNADIFFAREA 0.708600 ;
    PORT
      LAYER Metal3 ;
        RECT 215.580 134.620 215.980 135.020 ;
    END
  END q_o[76]
  PIN q_o[77]
    DIRECTION OUTPUT ;
    USE SIGNAL ;
    ANTENNADIFFAREA 0.708600 ;
    PORT
      LAYER Metal2 ;
        RECT 103.960 0.000 104.360 0.400 ;
    END
  END q_o[77]
  PIN q_o[78]
    DIRECTION OUTPUT ;
    USE SIGNAL ;
    ANTENNADIFFAREA 0.708600 ;
    PORT
      LAYER Metal3 ;
        RECT 0.000 97.660 0.400 98.060 ;
    END
  END q_o[78]
  PIN q_o[79]
    DIRECTION OUTPUT ;
    USE SIGNAL ;
    ANTENNADIFFAREA 0.708600 ;
    PORT
      LAYER Metal2 ;
        RECT 197.080 0.000 197.480 0.400 ;
    END
  END q_o[79]
  PIN q_o[7]
    DIRECTION OUTPUT ;
    USE SIGNAL ;
    ANTENNADIFFAREA 0.708600 ;
    PORT
      LAYER Metal2 ;
        RECT 7.960 234.300 8.360 234.700 ;
    END
  END q_o[7]
  PIN q_o[80]
    DIRECTION OUTPUT ;
    USE SIGNAL ;
    ANTENNADIFFAREA 0.708600 ;
    PORT
      LAYER Metal3 ;
        RECT 215.580 98.500 215.980 98.900 ;
    END
  END q_o[80]
  PIN q_o[81]
    DIRECTION OUTPUT ;
    USE SIGNAL ;
    ANTENNADIFFAREA 0.708600 ;
    PORT
      LAYER Metal2 ;
        RECT 201.880 0.000 202.280 0.400 ;
    END
  END q_o[81]
  PIN q_o[82]
    DIRECTION OUTPUT ;
    USE SIGNAL ;
    ANTENNADIFFAREA 0.708600 ;
    PORT
      LAYER Metal2 ;
        RECT 68.440 234.300 68.840 234.700 ;
    END
  END q_o[82]
  PIN q_o[83]
    DIRECTION OUTPUT ;
    USE SIGNAL ;
    ANTENNADIFFAREA 0.708600 ;
    PORT
      LAYER Metal3 ;
        RECT 215.580 138.820 215.980 139.220 ;
    END
  END q_o[83]
  PIN q_o[84]
    DIRECTION OUTPUT ;
    USE SIGNAL ;
    ANTENNADIFFAREA 0.708600 ;
    PORT
      LAYER Metal3 ;
        RECT 0.000 62.380 0.400 62.780 ;
    END
  END q_o[84]
  PIN q_o[85]
    DIRECTION OUTPUT ;
    USE SIGNAL ;
    ANTENNADIFFAREA 0.708600 ;
    PORT
      LAYER Metal3 ;
        RECT 0.000 131.260 0.400 131.660 ;
    END
  END q_o[85]
  PIN q_o[86]
    DIRECTION OUTPUT ;
    USE SIGNAL ;
    ANTENNADIFFAREA 0.708600 ;
    PORT
      LAYER Metal3 ;
        RECT 215.580 117.820 215.980 118.220 ;
    END
  END q_o[86]
  PIN q_o[87]
    DIRECTION OUTPUT ;
    USE SIGNAL ;
    ANTENNADIFFAREA 0.708600 ;
    PORT
      LAYER Metal3 ;
        RECT 0.000 155.620 0.400 156.020 ;
    END
  END q_o[87]
  PIN q_o[88]
    DIRECTION OUTPUT ;
    USE SIGNAL ;
    ANTENNADIFFAREA 0.708600 ;
    PORT
      LAYER Metal3 ;
        RECT 0.000 44.740 0.400 45.140 ;
    END
  END q_o[88]
  PIN q_o[89]
    DIRECTION OUTPUT ;
    USE SIGNAL ;
    ANTENNADIFFAREA 0.708600 ;
    PORT
      LAYER Metal2 ;
        RECT 121.240 0.000 121.640 0.400 ;
    END
  END q_o[89]
  PIN q_o[8]
    DIRECTION OUTPUT ;
    USE SIGNAL ;
    ANTENNADIFFAREA 0.708600 ;
    PORT
      LAYER Metal2 ;
        RECT 16.600 234.300 17.000 234.700 ;
    END
  END q_o[8]
  PIN q_o[90]
    DIRECTION OUTPUT ;
    USE SIGNAL ;
    ANTENNADIFFAREA 0.708600 ;
    PORT
      LAYER Metal2 ;
        RECT 147.160 234.300 147.560 234.700 ;
    END
  END q_o[90]
  PIN q_o[91]
    DIRECTION OUTPUT ;
    USE SIGNAL ;
    ANTENNADIFFAREA 0.708600 ;
    PORT
      LAYER Metal3 ;
        RECT 215.580 104.380 215.980 104.780 ;
    END
  END q_o[91]
  PIN q_o[92]
    DIRECTION OUTPUT ;
    USE SIGNAL ;
    ANTENNADIFFAREA 0.708600 ;
    PORT
      LAYER Metal2 ;
        RECT 103.000 234.300 103.400 234.700 ;
    END
  END q_o[92]
  PIN q_o[93]
    DIRECTION OUTPUT ;
    USE SIGNAL ;
    ANTENNADIFFAREA 0.708600 ;
    PORT
      LAYER Metal3 ;
        RECT 215.580 58.180 215.980 58.580 ;
    END
  END q_o[93]
  PIN q_o[94]
    DIRECTION OUTPUT ;
    USE SIGNAL ;
    ANTENNADIFFAREA 0.708600 ;
    PORT
      LAYER Metal3 ;
        RECT 215.580 126.220 215.980 126.620 ;
    END
  END q_o[94]
  PIN q_o[95]
    DIRECTION OUTPUT ;
    USE SIGNAL ;
    ANTENNADIFFAREA 0.708600 ;
    PORT
      LAYER Metal2 ;
        RECT 72.280 0.000 72.680 0.400 ;
    END
  END q_o[95]
  PIN q_o[96]
    DIRECTION OUTPUT ;
    USE SIGNAL ;
    ANTENNADIFFAREA 0.708600 ;
    PORT
      LAYER Metal2 ;
        RECT 67.480 234.300 67.880 234.700 ;
    END
  END q_o[96]
  PIN q_o[97]
    DIRECTION OUTPUT ;
    USE SIGNAL ;
    ANTENNADIFFAREA 0.708600 ;
    PORT
      LAYER Metal3 ;
        RECT 215.580 73.300 215.980 73.700 ;
    END
  END q_o[97]
  PIN q_o[98]
    DIRECTION OUTPUT ;
    USE SIGNAL ;
    ANTENNADIFFAREA 0.708600 ;
    PORT
      LAYER Metal2 ;
        RECT 126.040 234.300 126.440 234.700 ;
    END
  END q_o[98]
  PIN q_o[99]
    DIRECTION OUTPUT ;
    USE SIGNAL ;
    ANTENNADIFFAREA 0.708600 ;
    PORT
      LAYER Metal2 ;
        RECT 104.920 0.000 105.320 0.400 ;
    END
  END q_o[99]
  PIN q_o[9]
    DIRECTION OUTPUT ;
    USE SIGNAL ;
    ANTENNADIFFAREA 0.708600 ;
    PORT
      LAYER Metal3 ;
        RECT 215.580 183.340 215.980 183.740 ;
    END
  END q_o[9]
  PIN rst_n
    DIRECTION INPUT ;
    USE SIGNAL ;
    ANTENNAGATEAREA 0.180700 ;
    PORT
      LAYER Metal3 ;
        RECT 0.000 198.460 0.400 198.860 ;
    END
  END rst_n
  OBS
      LAYER GatPoly ;
        RECT 5.760 14.970 209.760 219.390 ;
      LAYER Metal1 ;
        RECT 5.760 14.900 209.760 219.460 ;
      LAYER Metal2 ;
        RECT 0.375 234.090 3.910 234.600 ;
        RECT 4.730 234.090 4.870 234.600 ;
        RECT 5.690 234.090 5.830 234.600 ;
        RECT 6.650 234.090 6.790 234.600 ;
        RECT 7.610 234.090 7.750 234.600 ;
        RECT 8.570 234.090 8.710 234.600 ;
        RECT 9.530 234.090 9.670 234.600 ;
        RECT 10.490 234.090 10.630 234.600 ;
        RECT 11.450 234.090 11.590 234.600 ;
        RECT 12.410 234.090 12.550 234.600 ;
        RECT 13.370 234.090 13.510 234.600 ;
        RECT 14.330 234.090 14.470 234.600 ;
        RECT 15.290 234.090 15.430 234.600 ;
        RECT 16.250 234.090 16.390 234.600 ;
        RECT 17.210 234.090 17.350 234.600 ;
        RECT 18.170 234.090 18.310 234.600 ;
        RECT 19.130 234.090 19.270 234.600 ;
        RECT 20.090 234.090 20.230 234.600 ;
        RECT 21.050 234.090 21.190 234.600 ;
        RECT 22.010 234.090 65.350 234.600 ;
        RECT 66.170 234.090 67.270 234.600 ;
        RECT 68.090 234.090 68.230 234.600 ;
        RECT 69.050 234.090 69.190 234.600 ;
        RECT 70.010 234.090 73.030 234.600 ;
        RECT 73.850 234.090 73.990 234.600 ;
        RECT 74.810 234.090 75.910 234.600 ;
        RECT 76.730 234.090 76.870 234.600 ;
        RECT 77.690 234.090 81.670 234.600 ;
        RECT 82.490 234.090 82.630 234.600 ;
        RECT 83.450 234.090 83.590 234.600 ;
        RECT 84.410 234.090 84.550 234.600 ;
        RECT 85.370 234.090 85.510 234.600 ;
        RECT 86.330 234.090 86.470 234.600 ;
        RECT 87.290 234.090 87.430 234.600 ;
        RECT 88.250 234.090 88.390 234.600 ;
        RECT 89.210 234.090 89.350 234.600 ;
        RECT 90.170 234.090 90.310 234.600 ;
        RECT 91.130 234.090 91.270 234.600 ;
        RECT 92.090 234.090 92.230 234.600 ;
        RECT 93.050 234.090 93.190 234.600 ;
        RECT 94.010 234.090 94.150 234.600 ;
        RECT 94.970 234.090 95.110 234.600 ;
        RECT 95.930 234.090 96.070 234.600 ;
        RECT 96.890 234.090 97.030 234.600 ;
        RECT 97.850 234.090 97.990 234.600 ;
        RECT 98.810 234.090 98.950 234.600 ;
        RECT 99.770 234.090 99.910 234.600 ;
        RECT 100.730 234.090 100.870 234.600 ;
        RECT 101.690 234.090 101.830 234.600 ;
        RECT 102.650 234.090 102.790 234.600 ;
        RECT 103.610 234.090 103.750 234.600 ;
        RECT 104.570 234.090 104.710 234.600 ;
        RECT 105.530 234.090 105.670 234.600 ;
        RECT 106.490 234.090 106.630 234.600 ;
        RECT 107.450 234.090 107.590 234.600 ;
        RECT 108.410 234.090 108.550 234.600 ;
        RECT 109.370 234.090 109.510 234.600 ;
        RECT 110.330 234.090 110.470 234.600 ;
        RECT 111.290 234.090 111.430 234.600 ;
        RECT 112.250 234.090 112.390 234.600 ;
        RECT 113.210 234.090 113.350 234.600 ;
        RECT 114.170 234.090 114.310 234.600 ;
        RECT 115.130 234.090 115.270 234.600 ;
        RECT 116.090 234.090 116.230 234.600 ;
        RECT 117.050 234.090 117.190 234.600 ;
        RECT 118.010 234.090 118.150 234.600 ;
        RECT 118.970 234.090 119.110 234.600 ;
        RECT 119.930 234.090 120.070 234.600 ;
        RECT 120.890 234.090 121.030 234.600 ;
        RECT 121.850 234.090 121.990 234.600 ;
        RECT 122.810 234.090 122.950 234.600 ;
        RECT 123.770 234.090 123.910 234.600 ;
        RECT 124.730 234.090 124.870 234.600 ;
        RECT 125.690 234.090 125.830 234.600 ;
        RECT 126.650 234.090 126.790 234.600 ;
        RECT 127.610 234.090 127.750 234.600 ;
        RECT 128.570 234.090 128.710 234.600 ;
        RECT 129.530 234.090 129.670 234.600 ;
        RECT 130.490 234.090 130.630 234.600 ;
        RECT 131.450 234.090 131.590 234.600 ;
        RECT 132.410 234.090 132.550 234.600 ;
        RECT 133.370 234.090 133.510 234.600 ;
        RECT 134.330 234.090 134.470 234.600 ;
        RECT 135.290 234.090 135.430 234.600 ;
        RECT 136.250 234.090 136.390 234.600 ;
        RECT 137.210 234.090 137.350 234.600 ;
        RECT 138.170 234.090 138.310 234.600 ;
        RECT 139.130 234.090 139.270 234.600 ;
        RECT 140.090 234.090 140.230 234.600 ;
        RECT 141.050 234.090 141.190 234.600 ;
        RECT 142.010 234.090 142.150 234.600 ;
        RECT 142.970 234.090 143.110 234.600 ;
        RECT 143.930 234.090 144.070 234.600 ;
        RECT 144.890 234.090 145.030 234.600 ;
        RECT 145.850 234.090 145.990 234.600 ;
        RECT 146.810 234.090 146.950 234.600 ;
        RECT 147.770 234.090 147.910 234.600 ;
        RECT 148.730 234.090 148.870 234.600 ;
        RECT 149.690 234.090 149.830 234.600 ;
        RECT 150.650 234.090 150.790 234.600 ;
        RECT 151.610 234.090 151.750 234.600 ;
        RECT 152.570 234.090 152.710 234.600 ;
        RECT 153.530 234.090 153.670 234.600 ;
        RECT 154.490 234.090 215.625 234.600 ;
        RECT 0.375 0.610 215.625 234.090 ;
        RECT 0.375 0.100 59.590 0.610 ;
        RECT 60.410 0.100 60.550 0.610 ;
        RECT 61.370 0.100 61.510 0.610 ;
        RECT 62.330 0.100 62.470 0.610 ;
        RECT 63.290 0.100 63.430 0.610 ;
        RECT 64.250 0.100 64.390 0.610 ;
        RECT 65.210 0.100 65.350 0.610 ;
        RECT 66.170 0.100 66.310 0.610 ;
        RECT 67.130 0.100 67.270 0.610 ;
        RECT 68.090 0.100 68.230 0.610 ;
        RECT 69.050 0.100 69.190 0.610 ;
        RECT 70.010 0.100 70.150 0.610 ;
        RECT 70.970 0.100 71.110 0.610 ;
        RECT 71.930 0.100 72.070 0.610 ;
        RECT 72.890 0.100 73.030 0.610 ;
        RECT 73.850 0.100 73.990 0.610 ;
        RECT 74.810 0.100 74.950 0.610 ;
        RECT 75.770 0.100 75.910 0.610 ;
        RECT 76.730 0.100 76.870 0.610 ;
        RECT 77.690 0.100 77.830 0.610 ;
        RECT 78.650 0.100 78.790 0.610 ;
        RECT 79.610 0.100 79.750 0.610 ;
        RECT 80.570 0.100 80.710 0.610 ;
        RECT 81.530 0.100 81.670 0.610 ;
        RECT 82.490 0.100 82.630 0.610 ;
        RECT 83.450 0.100 83.590 0.610 ;
        RECT 84.410 0.100 84.550 0.610 ;
        RECT 85.370 0.100 85.510 0.610 ;
        RECT 86.330 0.100 86.470 0.610 ;
        RECT 87.290 0.100 87.430 0.610 ;
        RECT 88.250 0.100 88.390 0.610 ;
        RECT 89.210 0.100 89.350 0.610 ;
        RECT 90.170 0.100 90.310 0.610 ;
        RECT 91.130 0.100 91.270 0.610 ;
        RECT 92.090 0.100 92.230 0.610 ;
        RECT 93.050 0.100 93.190 0.610 ;
        RECT 94.010 0.100 94.150 0.610 ;
        RECT 94.970 0.100 95.110 0.610 ;
        RECT 95.930 0.100 96.070 0.610 ;
        RECT 96.890 0.100 97.030 0.610 ;
        RECT 97.850 0.100 97.990 0.610 ;
        RECT 98.810 0.100 98.950 0.610 ;
        RECT 99.770 0.100 99.910 0.610 ;
        RECT 100.730 0.100 100.870 0.610 ;
        RECT 101.690 0.100 101.830 0.610 ;
        RECT 102.650 0.100 102.790 0.610 ;
        RECT 103.610 0.100 103.750 0.610 ;
        RECT 104.570 0.100 104.710 0.610 ;
        RECT 105.530 0.100 105.670 0.610 ;
        RECT 106.490 0.100 106.630 0.610 ;
        RECT 107.450 0.100 107.590 0.610 ;
        RECT 108.410 0.100 108.550 0.610 ;
        RECT 109.370 0.100 109.510 0.610 ;
        RECT 110.330 0.100 110.470 0.610 ;
        RECT 111.290 0.100 111.430 0.610 ;
        RECT 112.250 0.100 112.390 0.610 ;
        RECT 113.210 0.100 113.350 0.610 ;
        RECT 114.170 0.100 114.310 0.610 ;
        RECT 115.130 0.100 115.270 0.610 ;
        RECT 116.090 0.100 116.230 0.610 ;
        RECT 117.050 0.100 117.190 0.610 ;
        RECT 118.010 0.100 118.150 0.610 ;
        RECT 118.970 0.100 119.110 0.610 ;
        RECT 119.930 0.100 120.070 0.610 ;
        RECT 120.890 0.100 121.030 0.610 ;
        RECT 121.850 0.100 121.990 0.610 ;
        RECT 122.810 0.100 122.950 0.610 ;
        RECT 123.770 0.100 123.910 0.610 ;
        RECT 124.730 0.100 124.870 0.610 ;
        RECT 125.690 0.100 125.830 0.610 ;
        RECT 126.650 0.100 126.790 0.610 ;
        RECT 127.610 0.100 127.750 0.610 ;
        RECT 128.570 0.100 128.710 0.610 ;
        RECT 129.530 0.100 129.670 0.610 ;
        RECT 130.490 0.100 130.630 0.610 ;
        RECT 131.450 0.100 131.590 0.610 ;
        RECT 132.410 0.100 132.550 0.610 ;
        RECT 133.370 0.100 133.510 0.610 ;
        RECT 134.330 0.100 134.470 0.610 ;
        RECT 135.290 0.100 135.430 0.610 ;
        RECT 136.250 0.100 136.390 0.610 ;
        RECT 137.210 0.100 137.350 0.610 ;
        RECT 138.170 0.100 138.310 0.610 ;
        RECT 139.130 0.100 140.230 0.610 ;
        RECT 141.050 0.100 144.070 0.610 ;
        RECT 144.890 0.100 145.030 0.610 ;
        RECT 145.850 0.100 148.870 0.610 ;
        RECT 149.690 0.100 193.990 0.610 ;
        RECT 194.810 0.100 194.950 0.610 ;
        RECT 195.770 0.100 195.910 0.610 ;
        RECT 196.730 0.100 196.870 0.610 ;
        RECT 197.690 0.100 197.830 0.610 ;
        RECT 198.650 0.100 198.790 0.610 ;
        RECT 199.610 0.100 199.750 0.610 ;
        RECT 200.570 0.100 200.710 0.610 ;
        RECT 201.530 0.100 201.670 0.610 ;
        RECT 202.490 0.100 202.630 0.610 ;
        RECT 203.450 0.100 203.590 0.610 ;
        RECT 204.410 0.100 204.550 0.610 ;
        RECT 205.370 0.100 205.510 0.610 ;
        RECT 206.330 0.100 206.470 0.610 ;
        RECT 207.290 0.100 207.430 0.610 ;
        RECT 208.250 0.100 208.390 0.610 ;
        RECT 209.210 0.100 209.350 0.610 ;
        RECT 210.170 0.100 210.310 0.610 ;
        RECT 211.130 0.100 215.625 0.610 ;
      LAYER Metal3 ;
        RECT 0.100 211.670 215.665 232.780 ;
        RECT 0.100 210.850 215.370 211.670 ;
        RECT 0.100 210.830 215.665 210.850 ;
        RECT 0.100 210.010 215.370 210.830 ;
        RECT 0.100 209.990 215.665 210.010 ;
        RECT 0.100 209.170 215.370 209.990 ;
        RECT 0.100 209.150 215.665 209.170 ;
        RECT 0.100 208.330 215.370 209.150 ;
        RECT 0.100 208.310 215.665 208.330 ;
        RECT 0.100 207.490 215.370 208.310 ;
        RECT 0.100 207.470 215.665 207.490 ;
        RECT 0.100 206.650 215.370 207.470 ;
        RECT 0.100 206.630 215.665 206.650 ;
        RECT 0.100 205.810 215.370 206.630 ;
        RECT 0.100 205.790 215.665 205.810 ;
        RECT 0.100 204.970 215.370 205.790 ;
        RECT 0.100 204.950 215.665 204.970 ;
        RECT 0.100 204.130 215.370 204.950 ;
        RECT 0.100 204.110 215.665 204.130 ;
        RECT 0.100 203.290 215.370 204.110 ;
        RECT 0.100 203.270 215.665 203.290 ;
        RECT 0.100 202.450 215.370 203.270 ;
        RECT 0.100 202.430 215.665 202.450 ;
        RECT 0.100 201.610 215.370 202.430 ;
        RECT 0.100 201.590 215.665 201.610 ;
        RECT 0.100 200.770 215.370 201.590 ;
        RECT 0.100 200.750 215.665 200.770 ;
        RECT 0.610 199.930 215.370 200.750 ;
        RECT 0.100 199.910 215.665 199.930 ;
        RECT 0.100 199.090 215.370 199.910 ;
        RECT 0.100 199.070 215.665 199.090 ;
        RECT 0.610 198.250 215.370 199.070 ;
        RECT 0.100 198.230 215.665 198.250 ;
        RECT 0.100 197.410 215.370 198.230 ;
        RECT 0.100 197.390 215.665 197.410 ;
        RECT 0.100 196.570 215.370 197.390 ;
        RECT 0.100 196.550 215.665 196.570 ;
        RECT 0.100 195.730 215.370 196.550 ;
        RECT 0.100 195.710 215.665 195.730 ;
        RECT 0.100 194.890 215.370 195.710 ;
        RECT 0.100 194.870 215.665 194.890 ;
        RECT 0.100 194.050 215.370 194.870 ;
        RECT 0.100 194.030 215.665 194.050 ;
        RECT 0.100 193.210 215.370 194.030 ;
        RECT 0.100 193.190 215.665 193.210 ;
        RECT 0.100 192.370 215.370 193.190 ;
        RECT 0.100 192.350 215.665 192.370 ;
        RECT 0.100 191.530 215.370 192.350 ;
        RECT 0.100 191.510 215.665 191.530 ;
        RECT 0.100 190.690 215.370 191.510 ;
        RECT 0.100 190.670 215.665 190.690 ;
        RECT 0.100 189.850 215.370 190.670 ;
        RECT 0.100 189.830 215.665 189.850 ;
        RECT 0.100 189.010 215.370 189.830 ;
        RECT 0.100 188.990 215.665 189.010 ;
        RECT 0.100 188.170 215.370 188.990 ;
        RECT 0.100 188.150 215.665 188.170 ;
        RECT 0.100 187.330 215.370 188.150 ;
        RECT 0.100 187.310 215.665 187.330 ;
        RECT 0.100 186.490 215.370 187.310 ;
        RECT 0.100 186.470 215.665 186.490 ;
        RECT 0.100 185.650 215.370 186.470 ;
        RECT 0.100 185.630 215.665 185.650 ;
        RECT 0.610 184.810 215.370 185.630 ;
        RECT 0.100 184.790 215.665 184.810 ;
        RECT 0.610 183.970 215.370 184.790 ;
        RECT 0.100 183.950 215.665 183.970 ;
        RECT 0.610 183.130 215.370 183.950 ;
        RECT 0.100 183.110 215.665 183.130 ;
        RECT 0.610 182.290 215.370 183.110 ;
        RECT 0.100 182.270 215.665 182.290 ;
        RECT 0.100 181.450 215.370 182.270 ;
        RECT 0.100 181.430 215.665 181.450 ;
        RECT 0.100 180.610 215.370 181.430 ;
        RECT 0.100 180.590 215.665 180.610 ;
        RECT 0.100 179.770 215.370 180.590 ;
        RECT 0.100 179.750 215.665 179.770 ;
        RECT 0.100 178.930 215.370 179.750 ;
        RECT 0.100 178.910 215.665 178.930 ;
        RECT 0.100 178.090 215.370 178.910 ;
        RECT 0.100 178.070 215.665 178.090 ;
        RECT 0.610 177.250 215.370 178.070 ;
        RECT 0.100 177.230 215.665 177.250 ;
        RECT 0.610 176.410 215.370 177.230 ;
        RECT 0.100 176.390 215.665 176.410 ;
        RECT 0.100 175.570 215.370 176.390 ;
        RECT 0.100 175.550 215.665 175.570 ;
        RECT 0.610 174.730 215.370 175.550 ;
        RECT 0.100 174.710 215.665 174.730 ;
        RECT 0.100 173.890 215.370 174.710 ;
        RECT 0.100 173.870 215.665 173.890 ;
        RECT 0.100 173.050 215.370 173.870 ;
        RECT 0.100 173.030 215.665 173.050 ;
        RECT 0.610 172.210 215.370 173.030 ;
        RECT 0.100 172.190 215.665 172.210 ;
        RECT 0.610 171.370 215.370 172.190 ;
        RECT 0.100 171.350 215.665 171.370 ;
        RECT 0.610 170.530 215.370 171.350 ;
        RECT 0.100 170.510 215.665 170.530 ;
        RECT 0.610 169.690 215.370 170.510 ;
        RECT 0.100 169.670 215.665 169.690 ;
        RECT 0.610 168.850 215.665 169.670 ;
        RECT 0.100 168.830 215.665 168.850 ;
        RECT 0.610 168.010 215.665 168.830 ;
        RECT 0.100 167.990 215.665 168.010 ;
        RECT 0.610 167.170 215.665 167.990 ;
        RECT 0.100 167.150 215.665 167.170 ;
        RECT 0.610 166.330 215.665 167.150 ;
        RECT 0.100 166.310 215.665 166.330 ;
        RECT 0.610 165.490 215.665 166.310 ;
        RECT 0.100 165.470 215.665 165.490 ;
        RECT 0.610 164.650 215.665 165.470 ;
        RECT 0.100 164.630 215.665 164.650 ;
        RECT 0.610 163.810 215.665 164.630 ;
        RECT 0.100 163.790 215.665 163.810 ;
        RECT 0.610 162.970 215.665 163.790 ;
        RECT 0.100 162.950 215.665 162.970 ;
        RECT 0.610 162.130 215.665 162.950 ;
        RECT 0.100 162.110 215.665 162.130 ;
        RECT 0.610 161.290 215.665 162.110 ;
        RECT 0.100 161.270 215.665 161.290 ;
        RECT 0.610 160.450 215.665 161.270 ;
        RECT 0.100 160.430 215.665 160.450 ;
        RECT 0.610 159.610 215.665 160.430 ;
        RECT 0.100 159.590 215.665 159.610 ;
        RECT 0.610 158.770 215.665 159.590 ;
        RECT 0.100 158.750 215.665 158.770 ;
        RECT 0.610 157.930 215.665 158.750 ;
        RECT 0.100 157.910 215.665 157.930 ;
        RECT 0.610 157.090 215.665 157.910 ;
        RECT 0.100 157.070 215.665 157.090 ;
        RECT 0.610 156.250 215.665 157.070 ;
        RECT 0.100 156.230 215.665 156.250 ;
        RECT 0.610 155.410 215.665 156.230 ;
        RECT 0.100 155.390 215.665 155.410 ;
        RECT 0.610 154.570 215.665 155.390 ;
        RECT 0.100 154.550 215.665 154.570 ;
        RECT 0.610 153.730 215.665 154.550 ;
        RECT 0.100 153.710 215.665 153.730 ;
        RECT 0.610 152.890 215.665 153.710 ;
        RECT 0.100 152.870 215.665 152.890 ;
        RECT 0.610 152.050 215.665 152.870 ;
        RECT 0.100 152.030 215.665 152.050 ;
        RECT 0.610 151.210 215.665 152.030 ;
        RECT 0.100 151.190 215.665 151.210 ;
        RECT 0.610 150.370 215.665 151.190 ;
        RECT 0.100 150.350 215.665 150.370 ;
        RECT 0.610 149.530 215.665 150.350 ;
        RECT 0.100 149.510 215.665 149.530 ;
        RECT 0.610 148.690 215.665 149.510 ;
        RECT 0.100 148.670 215.665 148.690 ;
        RECT 0.610 147.850 215.665 148.670 ;
        RECT 0.100 147.830 215.665 147.850 ;
        RECT 0.610 147.010 215.665 147.830 ;
        RECT 0.100 146.990 215.665 147.010 ;
        RECT 0.610 146.170 215.665 146.990 ;
        RECT 0.100 146.150 215.665 146.170 ;
        RECT 0.610 145.330 215.665 146.150 ;
        RECT 0.100 145.310 215.665 145.330 ;
        RECT 0.610 144.490 215.665 145.310 ;
        RECT 0.100 144.470 215.665 144.490 ;
        RECT 0.610 143.650 215.665 144.470 ;
        RECT 0.100 143.630 215.665 143.650 ;
        RECT 0.610 142.810 215.665 143.630 ;
        RECT 0.100 142.790 215.665 142.810 ;
        RECT 0.610 141.970 215.665 142.790 ;
        RECT 0.100 141.950 215.665 141.970 ;
        RECT 0.610 141.130 215.665 141.950 ;
        RECT 0.100 141.110 215.665 141.130 ;
        RECT 0.610 140.290 215.370 141.110 ;
        RECT 0.100 140.270 215.665 140.290 ;
        RECT 0.610 139.450 215.370 140.270 ;
        RECT 0.100 139.430 215.665 139.450 ;
        RECT 0.610 138.610 215.370 139.430 ;
        RECT 0.100 138.590 215.665 138.610 ;
        RECT 0.610 137.770 215.370 138.590 ;
        RECT 0.100 137.750 215.665 137.770 ;
        RECT 0.610 136.930 215.370 137.750 ;
        RECT 0.100 136.910 215.665 136.930 ;
        RECT 0.610 136.090 215.370 136.910 ;
        RECT 0.100 136.070 215.665 136.090 ;
        RECT 0.610 135.250 215.370 136.070 ;
        RECT 0.100 135.230 215.665 135.250 ;
        RECT 0.610 134.410 215.370 135.230 ;
        RECT 0.100 134.390 215.665 134.410 ;
        RECT 0.610 133.570 215.370 134.390 ;
        RECT 0.100 133.550 215.665 133.570 ;
        RECT 0.610 132.730 215.370 133.550 ;
        RECT 0.100 132.710 215.665 132.730 ;
        RECT 0.610 131.890 215.370 132.710 ;
        RECT 0.100 131.870 215.665 131.890 ;
        RECT 0.610 131.050 215.370 131.870 ;
        RECT 0.100 131.030 215.665 131.050 ;
        RECT 0.610 130.210 215.370 131.030 ;
        RECT 0.100 130.190 215.665 130.210 ;
        RECT 0.610 129.370 215.370 130.190 ;
        RECT 0.100 129.350 215.665 129.370 ;
        RECT 0.610 128.530 215.370 129.350 ;
        RECT 0.100 128.510 215.665 128.530 ;
        RECT 0.610 127.690 215.665 128.510 ;
        RECT 0.100 127.670 215.665 127.690 ;
        RECT 0.610 126.850 215.665 127.670 ;
        RECT 0.100 126.830 215.665 126.850 ;
        RECT 0.610 126.010 215.370 126.830 ;
        RECT 0.100 125.990 215.665 126.010 ;
        RECT 0.610 125.170 215.370 125.990 ;
        RECT 0.100 125.150 215.665 125.170 ;
        RECT 0.610 124.330 215.370 125.150 ;
        RECT 0.100 124.310 215.665 124.330 ;
        RECT 0.610 123.490 215.370 124.310 ;
        RECT 0.100 123.470 215.665 123.490 ;
        RECT 0.610 122.650 215.370 123.470 ;
        RECT 0.100 122.630 215.665 122.650 ;
        RECT 0.610 121.810 215.370 122.630 ;
        RECT 0.100 121.790 215.665 121.810 ;
        RECT 0.610 120.970 215.370 121.790 ;
        RECT 0.100 120.950 215.665 120.970 ;
        RECT 0.610 120.130 215.370 120.950 ;
        RECT 0.100 120.110 215.665 120.130 ;
        RECT 0.610 119.290 215.370 120.110 ;
        RECT 0.100 119.270 215.665 119.290 ;
        RECT 0.610 118.450 215.370 119.270 ;
        RECT 0.100 118.430 215.665 118.450 ;
        RECT 0.610 117.610 215.370 118.430 ;
        RECT 0.100 117.590 215.665 117.610 ;
        RECT 0.610 116.770 215.370 117.590 ;
        RECT 0.100 116.750 215.665 116.770 ;
        RECT 0.610 115.930 215.370 116.750 ;
        RECT 0.100 115.910 215.665 115.930 ;
        RECT 0.610 115.090 215.370 115.910 ;
        RECT 0.100 115.070 215.665 115.090 ;
        RECT 0.610 114.250 215.370 115.070 ;
        RECT 0.100 114.230 215.665 114.250 ;
        RECT 0.610 113.410 215.370 114.230 ;
        RECT 0.100 113.390 215.665 113.410 ;
        RECT 0.610 112.570 215.370 113.390 ;
        RECT 0.100 112.550 215.665 112.570 ;
        RECT 0.610 111.730 215.370 112.550 ;
        RECT 0.100 111.710 215.665 111.730 ;
        RECT 0.610 110.890 215.370 111.710 ;
        RECT 0.100 110.870 215.665 110.890 ;
        RECT 0.610 110.050 215.370 110.870 ;
        RECT 0.100 110.030 215.665 110.050 ;
        RECT 0.610 109.210 215.370 110.030 ;
        RECT 0.100 109.190 215.665 109.210 ;
        RECT 0.610 108.370 215.370 109.190 ;
        RECT 0.100 108.350 215.665 108.370 ;
        RECT 0.610 107.530 215.370 108.350 ;
        RECT 0.100 107.510 215.665 107.530 ;
        RECT 0.610 106.690 215.370 107.510 ;
        RECT 0.100 106.670 215.665 106.690 ;
        RECT 0.610 105.850 215.370 106.670 ;
        RECT 0.100 105.830 215.665 105.850 ;
        RECT 0.610 105.010 215.665 105.830 ;
        RECT 0.100 104.990 215.665 105.010 ;
        RECT 0.610 104.170 215.370 104.990 ;
        RECT 0.100 104.150 215.665 104.170 ;
        RECT 0.610 103.330 215.370 104.150 ;
        RECT 0.100 103.310 215.665 103.330 ;
        RECT 0.100 102.490 215.370 103.310 ;
        RECT 0.100 102.470 215.665 102.490 ;
        RECT 0.610 101.650 215.370 102.470 ;
        RECT 0.100 101.630 215.665 101.650 ;
        RECT 0.610 100.810 215.370 101.630 ;
        RECT 0.100 100.790 215.665 100.810 ;
        RECT 0.610 99.970 215.370 100.790 ;
        RECT 0.100 99.950 215.665 99.970 ;
        RECT 0.610 99.130 215.370 99.950 ;
        RECT 0.100 99.110 215.665 99.130 ;
        RECT 0.610 98.290 215.370 99.110 ;
        RECT 0.100 98.270 215.665 98.290 ;
        RECT 0.610 97.450 215.370 98.270 ;
        RECT 0.100 97.430 215.665 97.450 ;
        RECT 0.610 96.610 215.370 97.430 ;
        RECT 0.100 96.590 215.665 96.610 ;
        RECT 0.610 95.770 215.370 96.590 ;
        RECT 0.100 95.750 215.665 95.770 ;
        RECT 0.610 94.930 215.370 95.750 ;
        RECT 0.100 94.910 215.665 94.930 ;
        RECT 0.610 94.090 215.370 94.910 ;
        RECT 0.100 94.070 215.665 94.090 ;
        RECT 0.610 93.250 215.370 94.070 ;
        RECT 0.100 93.230 215.665 93.250 ;
        RECT 0.610 92.410 215.370 93.230 ;
        RECT 0.100 92.390 215.665 92.410 ;
        RECT 0.610 91.570 215.370 92.390 ;
        RECT 0.100 91.550 215.665 91.570 ;
        RECT 0.610 90.730 215.370 91.550 ;
        RECT 0.100 90.710 215.665 90.730 ;
        RECT 0.100 89.890 215.370 90.710 ;
        RECT 0.100 89.870 215.665 89.890 ;
        RECT 0.100 89.050 215.370 89.870 ;
        RECT 0.100 89.030 215.665 89.050 ;
        RECT 0.100 88.210 215.370 89.030 ;
        RECT 0.100 88.190 215.665 88.210 ;
        RECT 0.100 87.370 215.370 88.190 ;
        RECT 0.100 87.350 215.665 87.370 ;
        RECT 0.100 86.530 215.370 87.350 ;
        RECT 0.100 86.510 215.665 86.530 ;
        RECT 0.100 85.690 215.370 86.510 ;
        RECT 0.100 85.670 215.665 85.690 ;
        RECT 0.100 84.850 215.370 85.670 ;
        RECT 0.100 84.830 215.665 84.850 ;
        RECT 0.100 84.010 215.370 84.830 ;
        RECT 0.100 83.990 215.665 84.010 ;
        RECT 0.100 83.170 215.370 83.990 ;
        RECT 0.100 83.150 215.665 83.170 ;
        RECT 0.100 82.330 215.370 83.150 ;
        RECT 0.100 82.310 215.665 82.330 ;
        RECT 0.100 81.490 215.370 82.310 ;
        RECT 0.100 81.470 215.665 81.490 ;
        RECT 0.100 80.650 215.370 81.470 ;
        RECT 0.100 80.630 215.665 80.650 ;
        RECT 0.100 79.810 215.370 80.630 ;
        RECT 0.100 79.790 215.665 79.810 ;
        RECT 0.100 78.970 215.370 79.790 ;
        RECT 0.100 78.950 215.665 78.970 ;
        RECT 0.100 78.130 215.370 78.950 ;
        RECT 0.100 78.110 215.665 78.130 ;
        RECT 0.100 77.290 215.370 78.110 ;
        RECT 0.100 77.270 215.665 77.290 ;
        RECT 0.100 76.450 215.370 77.270 ;
        RECT 0.100 76.430 215.665 76.450 ;
        RECT 0.100 75.610 215.370 76.430 ;
        RECT 0.100 75.590 215.665 75.610 ;
        RECT 0.100 74.770 215.370 75.590 ;
        RECT 0.100 74.750 215.665 74.770 ;
        RECT 0.100 73.930 215.370 74.750 ;
        RECT 0.100 73.910 215.665 73.930 ;
        RECT 0.100 73.090 215.370 73.910 ;
        RECT 0.100 73.070 215.665 73.090 ;
        RECT 0.100 72.250 215.370 73.070 ;
        RECT 0.100 72.230 215.665 72.250 ;
        RECT 0.100 71.410 215.370 72.230 ;
        RECT 0.100 71.390 215.665 71.410 ;
        RECT 0.100 70.570 215.370 71.390 ;
        RECT 0.100 70.550 215.665 70.570 ;
        RECT 0.100 69.730 215.370 70.550 ;
        RECT 0.100 69.710 215.665 69.730 ;
        RECT 0.100 68.890 215.370 69.710 ;
        RECT 0.100 68.870 215.665 68.890 ;
        RECT 0.100 68.050 215.370 68.870 ;
        RECT 0.100 68.030 215.665 68.050 ;
        RECT 0.100 67.210 215.370 68.030 ;
        RECT 0.100 67.190 215.665 67.210 ;
        RECT 0.100 66.370 215.370 67.190 ;
        RECT 0.100 66.350 215.665 66.370 ;
        RECT 0.100 65.530 215.370 66.350 ;
        RECT 0.100 65.510 215.665 65.530 ;
        RECT 0.100 64.690 215.370 65.510 ;
        RECT 0.100 64.670 215.665 64.690 ;
        RECT 0.610 63.850 215.370 64.670 ;
        RECT 0.100 63.830 215.665 63.850 ;
        RECT 0.610 63.010 215.370 63.830 ;
        RECT 0.100 62.990 215.665 63.010 ;
        RECT 0.610 62.170 215.665 62.990 ;
        RECT 0.100 62.150 215.665 62.170 ;
        RECT 0.610 61.330 215.665 62.150 ;
        RECT 0.100 61.310 215.665 61.330 ;
        RECT 0.610 60.490 215.665 61.310 ;
        RECT 0.100 60.470 215.665 60.490 ;
        RECT 0.610 59.650 215.370 60.470 ;
        RECT 0.100 59.630 215.665 59.650 ;
        RECT 0.610 58.810 215.370 59.630 ;
        RECT 0.100 58.790 215.665 58.810 ;
        RECT 0.610 57.970 215.370 58.790 ;
        RECT 0.100 57.950 215.665 57.970 ;
        RECT 0.610 57.130 215.370 57.950 ;
        RECT 0.100 57.110 215.665 57.130 ;
        RECT 0.610 56.290 215.370 57.110 ;
        RECT 0.100 56.270 215.665 56.290 ;
        RECT 0.610 55.450 215.370 56.270 ;
        RECT 0.100 55.430 215.665 55.450 ;
        RECT 0.610 54.610 215.370 55.430 ;
        RECT 0.100 54.590 215.665 54.610 ;
        RECT 0.610 53.770 215.370 54.590 ;
        RECT 0.100 53.750 215.665 53.770 ;
        RECT 0.610 52.930 215.370 53.750 ;
        RECT 0.100 52.910 215.665 52.930 ;
        RECT 0.610 52.090 215.370 52.910 ;
        RECT 0.100 52.070 215.665 52.090 ;
        RECT 0.610 51.250 215.370 52.070 ;
        RECT 0.100 51.230 215.665 51.250 ;
        RECT 0.610 50.410 215.370 51.230 ;
        RECT 0.100 50.390 215.665 50.410 ;
        RECT 0.610 49.570 215.665 50.390 ;
        RECT 0.100 49.550 215.665 49.570 ;
        RECT 0.610 48.730 215.665 49.550 ;
        RECT 0.100 48.710 215.665 48.730 ;
        RECT 0.610 47.890 215.665 48.710 ;
        RECT 0.100 47.870 215.665 47.890 ;
        RECT 0.610 47.050 215.665 47.870 ;
        RECT 0.100 47.030 215.665 47.050 ;
        RECT 0.610 46.210 215.665 47.030 ;
        RECT 0.100 46.190 215.665 46.210 ;
        RECT 0.610 45.370 215.665 46.190 ;
        RECT 0.100 45.350 215.665 45.370 ;
        RECT 0.610 44.530 215.665 45.350 ;
        RECT 0.100 44.510 215.665 44.530 ;
        RECT 0.610 43.690 215.665 44.510 ;
        RECT 0.100 43.670 215.665 43.690 ;
        RECT 0.610 42.850 215.665 43.670 ;
        RECT 0.100 42.830 215.665 42.850 ;
        RECT 0.610 42.010 215.665 42.830 ;
        RECT 0.100 41.990 215.665 42.010 ;
        RECT 0.610 41.170 215.665 41.990 ;
        RECT 0.100 41.150 215.665 41.170 ;
        RECT 0.610 40.330 215.665 41.150 ;
        RECT 0.100 40.310 215.665 40.330 ;
        RECT 0.610 39.490 215.665 40.310 ;
        RECT 0.100 39.470 215.665 39.490 ;
        RECT 0.610 38.650 215.665 39.470 ;
        RECT 0.100 38.630 215.665 38.650 ;
        RECT 0.610 37.810 215.665 38.630 ;
        RECT 0.100 37.790 215.665 37.810 ;
        RECT 0.610 36.970 215.665 37.790 ;
        RECT 0.100 36.950 215.665 36.970 ;
        RECT 0.610 36.130 215.665 36.950 ;
        RECT 0.100 36.110 215.665 36.130 ;
        RECT 0.610 35.290 215.665 36.110 ;
        RECT 0.100 35.270 215.665 35.290 ;
        RECT 0.610 34.450 215.665 35.270 ;
        RECT 0.100 34.430 215.665 34.450 ;
        RECT 0.610 33.610 215.665 34.430 ;
        RECT 0.100 33.590 215.665 33.610 ;
        RECT 0.610 32.770 215.665 33.590 ;
        RECT 0.100 32.750 215.665 32.770 ;
        RECT 0.610 31.930 215.665 32.750 ;
        RECT 0.100 31.910 215.665 31.930 ;
        RECT 0.610 31.090 215.665 31.910 ;
        RECT 0.100 31.070 215.665 31.090 ;
        RECT 0.610 30.250 215.665 31.070 ;
        RECT 0.100 30.230 215.665 30.250 ;
        RECT 0.610 29.410 215.665 30.230 ;
        RECT 0.100 29.390 215.665 29.410 ;
        RECT 0.610 28.570 215.665 29.390 ;
        RECT 0.100 28.550 215.665 28.570 ;
        RECT 0.610 27.730 215.665 28.550 ;
        RECT 0.100 27.710 215.665 27.730 ;
        RECT 0.610 26.890 215.665 27.710 ;
        RECT 0.100 26.870 215.665 26.890 ;
        RECT 0.610 26.050 215.665 26.870 ;
        RECT 0.100 26.030 215.665 26.050 ;
        RECT 0.610 25.210 215.665 26.030 ;
        RECT 0.100 25.190 215.665 25.210 ;
        RECT 0.610 24.370 215.665 25.190 ;
        RECT 0.100 0.320 215.665 24.370 ;
      LAYER Metal4 ;
        RECT 4.220 13.715 214.660 225.685 ;
      LAYER Metal5 ;
        RECT 8.975 14.810 208.465 219.550 ;
  END
END zirh_tmr_ff256
END LIBRARY

